VERSION 5.7 ;
BUSBITCHARS "[]" ;
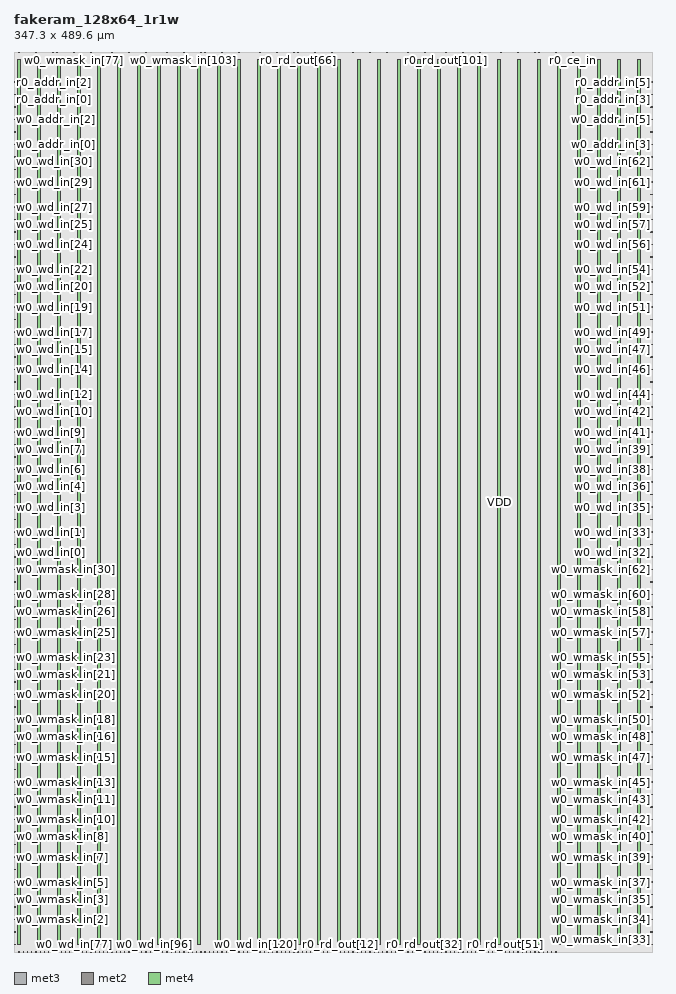
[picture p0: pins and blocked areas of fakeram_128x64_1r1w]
MACRO fakeram_128x64_1r1w
  FOREIGN fakeram_128x64_1r1w 0 0 ;
  SYMMETRY X Y R90 ;
  SIZE 347.300 BY 489.600 ;
  CLASS BLOCK ;
  PIN w0_wmask_in[0]
    DIRECTION INPUT ;
    USE SIGNAL ;
    SHAPE ABUTMENT ;
    PORT
      LAYER met3 ;
      RECT 0.000 3.930 0.900 4.230 ;
    END
  END w0_wmask_in[0]
  PIN w0_wmask_in[1]
    DIRECTION INPUT ;
    USE SIGNAL ;
    SHAPE ABUTMENT ;
    PORT
      LAYER met3 ;
      RECT 0.000 10.730 0.900 11.030 ;
    END
  END w0_wmask_in[1]
  PIN w0_wmask_in[2]
    DIRECTION INPUT ;
    USE SIGNAL ;
    SHAPE ABUTMENT ;
    PORT
      LAYER met3 ;
      RECT 0.000 17.530 0.900 17.830 ;
    END
  END w0_wmask_in[2]
  PIN w0_wmask_in[3]
    DIRECTION INPUT ;
    USE SIGNAL ;
    SHAPE ABUTMENT ;
    PORT
      LAYER met3 ;
      RECT 0.000 24.330 0.900 24.630 ;
    END
  END w0_wmask_in[3]
  PIN w0_wmask_in[4]
    DIRECTION INPUT ;
    USE SIGNAL ;
    SHAPE ABUTMENT ;
    PORT
      LAYER met3 ;
      RECT 0.000 31.130 0.900 31.430 ;
    END
  END w0_wmask_in[4]
  PIN w0_wmask_in[5]
    DIRECTION INPUT ;
    USE SIGNAL ;
    SHAPE ABUTMENT ;
    PORT
      LAYER met3 ;
      RECT 0.000 37.930 0.900 38.230 ;
    END
  END w0_wmask_in[5]
  PIN w0_wmask_in[6]
    DIRECTION INPUT ;
    USE SIGNAL ;
    SHAPE ABUTMENT ;
    PORT
      LAYER met3 ;
      RECT 0.000 44.730 0.900 45.030 ;
    END
  END w0_wmask_in[6]
  PIN w0_wmask_in[7]
    DIRECTION INPUT ;
    USE SIGNAL ;
    SHAPE ABUTMENT ;
    PORT
      LAYER met3 ;
      RECT 0.000 51.530 0.900 51.830 ;
    END
  END w0_wmask_in[7]
  PIN w0_wmask_in[8]
    DIRECTION INPUT ;
    USE SIGNAL ;
    SHAPE ABUTMENT ;
    PORT
      LAYER met3 ;
      RECT 0.000 58.330 0.900 58.630 ;
    END
  END w0_wmask_in[8]
  PIN w0_wmask_in[9]
    DIRECTION INPUT ;
    USE SIGNAL ;
    SHAPE ABUTMENT ;
    PORT
      LAYER met3 ;
      RECT 0.000 65.130 0.900 65.430 ;
    END
  END w0_wmask_in[9]
  PIN w0_wmask_in[10]
    DIRECTION INPUT ;
    USE SIGNAL ;
    SHAPE ABUTMENT ;
    PORT
      LAYER met3 ;
      RECT 0.000 71.930 0.900 72.230 ;
    END
  END w0_wmask_in[10]
  PIN w0_wmask_in[11]
    DIRECTION INPUT ;
    USE SIGNAL ;
    SHAPE ABUTMENT ;
    PORT
      LAYER met3 ;
      RECT 0.000 78.730 0.900 79.030 ;
    END
  END w0_wmask_in[11]
  PIN w0_wmask_in[12]
    DIRECTION INPUT ;
    USE SIGNAL ;
    SHAPE ABUTMENT ;
    PORT
      LAYER met3 ;
      RECT 0.000 85.530 0.900 85.830 ;
    END
  END w0_wmask_in[12]
  PIN w0_wmask_in[13]
    DIRECTION INPUT ;
    USE SIGNAL ;
    SHAPE ABUTMENT ;
    PORT
      LAYER met3 ;
      RECT 0.000 92.330 0.900 92.630 ;
    END
  END w0_wmask_in[13]
  PIN w0_wmask_in[14]
    DIRECTION INPUT ;
    USE SIGNAL ;
    SHAPE ABUTMENT ;
    PORT
      LAYER met3 ;
      RECT 0.000 99.130 0.900 99.430 ;
    END
  END w0_wmask_in[14]
  PIN w0_wmask_in[15]
    DIRECTION INPUT ;
    USE SIGNAL ;
    SHAPE ABUTMENT ;
    PORT
      LAYER met3 ;
      RECT 0.000 105.930 0.900 106.230 ;
    END
  END w0_wmask_in[15]
  PIN w0_wmask_in[16]
    DIRECTION INPUT ;
    USE SIGNAL ;
    SHAPE ABUTMENT ;
    PORT
      LAYER met3 ;
      RECT 0.000 112.730 0.900 113.030 ;
    END
  END w0_wmask_in[16]
  PIN w0_wmask_in[17]
    DIRECTION INPUT ;
    USE SIGNAL ;
    SHAPE ABUTMENT ;
    PORT
      LAYER met3 ;
      RECT 0.000 119.530 0.900 119.830 ;
    END
  END w0_wmask_in[17]
  PIN w0_wmask_in[18]
    DIRECTION INPUT ;
    USE SIGNAL ;
    SHAPE ABUTMENT ;
    PORT
      LAYER met3 ;
      RECT 0.000 126.330 0.900 126.630 ;
    END
  END w0_wmask_in[18]
  PIN w0_wmask_in[19]
    DIRECTION INPUT ;
    USE SIGNAL ;
    SHAPE ABUTMENT ;
    PORT
      LAYER met3 ;
      RECT 0.000 133.130 0.900 133.430 ;
    END
  END w0_wmask_in[19]
  PIN w0_wmask_in[20]
    DIRECTION INPUT ;
    USE SIGNAL ;
    SHAPE ABUTMENT ;
    PORT
      LAYER met3 ;
      RECT 0.000 139.930 0.900 140.230 ;
    END
  END w0_wmask_in[20]
  PIN w0_wmask_in[21]
    DIRECTION INPUT ;
    USE SIGNAL ;
    SHAPE ABUTMENT ;
    PORT
      LAYER met3 ;
      RECT 0.000 146.730 0.900 147.030 ;
    END
  END w0_wmask_in[21]
  PIN w0_wmask_in[22]
    DIRECTION INPUT ;
    USE SIGNAL ;
    SHAPE ABUTMENT ;
    PORT
      LAYER met3 ;
      RECT 0.000 153.530 0.900 153.830 ;
    END
  END w0_wmask_in[22]
  PIN w0_wmask_in[23]
    DIRECTION INPUT ;
    USE SIGNAL ;
    SHAPE ABUTMENT ;
    PORT
      LAYER met3 ;
      RECT 0.000 160.330 0.900 160.630 ;
    END
  END w0_wmask_in[23]
  PIN w0_wmask_in[24]
    DIRECTION INPUT ;
    USE SIGNAL ;
    SHAPE ABUTMENT ;
    PORT
      LAYER met3 ;
      RECT 0.000 167.130 0.900 167.430 ;
    END
  END w0_wmask_in[24]
  PIN w0_wmask_in[25]
    DIRECTION INPUT ;
    USE SIGNAL ;
    SHAPE ABUTMENT ;
    PORT
      LAYER met3 ;
      RECT 0.000 173.930 0.900 174.230 ;
    END
  END w0_wmask_in[25]
  PIN w0_wmask_in[26]
    DIRECTION INPUT ;
    USE SIGNAL ;
    SHAPE ABUTMENT ;
    PORT
      LAYER met3 ;
      RECT 0.000 180.730 0.900 181.030 ;
    END
  END w0_wmask_in[26]
  PIN w0_wmask_in[27]
    DIRECTION INPUT ;
    USE SIGNAL ;
    SHAPE ABUTMENT ;
    PORT
      LAYER met3 ;
      RECT 0.000 187.530 0.900 187.830 ;
    END
  END w0_wmask_in[27]
  PIN w0_wmask_in[28]
    DIRECTION INPUT ;
    USE SIGNAL ;
    SHAPE ABUTMENT ;
    PORT
      LAYER met3 ;
      RECT 0.000 194.330 0.900 194.630 ;
    END
  END w0_wmask_in[28]
  PIN w0_wmask_in[29]
    DIRECTION INPUT ;
    USE SIGNAL ;
    SHAPE ABUTMENT ;
    PORT
      LAYER met3 ;
      RECT 0.000 201.130 0.900 201.430 ;
    END
  END w0_wmask_in[29]
  PIN w0_wmask_in[30]
    DIRECTION INPUT ;
    USE SIGNAL ;
    SHAPE ABUTMENT ;
    PORT
      LAYER met3 ;
      RECT 0.000 207.930 0.900 208.230 ;
    END
  END w0_wmask_in[30]
  PIN w0_wmask_in[31]
    DIRECTION INPUT ;
    USE SIGNAL ;
    SHAPE ABUTMENT ;
    PORT
      LAYER met3 ;
      RECT 0.000 214.730 0.900 215.030 ;
    END
  END w0_wmask_in[31]
  PIN w0_wmask_in[32]
    DIRECTION INPUT ;
    USE SIGNAL ;
    SHAPE ABUTMENT ;
    PORT
      LAYER met3 ;
      RECT 346.400 3.930 347.300 4.230 ;
    END
  END w0_wmask_in[32]
  PIN w0_wmask_in[33]
    DIRECTION INPUT ;
    USE SIGNAL ;
    SHAPE ABUTMENT ;
    PORT
      LAYER met3 ;
      RECT 346.400 10.730 347.300 11.030 ;
    END
  END w0_wmask_in[33]
  PIN w0_wmask_in[34]
    DIRECTION INPUT ;
    USE SIGNAL ;
    SHAPE ABUTMENT ;
    PORT
      LAYER met3 ;
      RECT 346.400 17.530 347.300 17.830 ;
    END
  END w0_wmask_in[34]
  PIN w0_wmask_in[35]
    DIRECTION INPUT ;
    USE SIGNAL ;
    SHAPE ABUTMENT ;
    PORT
      LAYER met3 ;
      RECT 346.400 24.330 347.300 24.630 ;
    END
  END w0_wmask_in[35]
  PIN w0_wmask_in[36]
    DIRECTION INPUT ;
    USE SIGNAL ;
    SHAPE ABUTMENT ;
    PORT
      LAYER met3 ;
      RECT 346.400 31.130 347.300 31.430 ;
    END
  END w0_wmask_in[36]
  PIN w0_wmask_in[37]
    DIRECTION INPUT ;
    USE SIGNAL ;
    SHAPE ABUTMENT ;
    PORT
      LAYER met3 ;
      RECT 346.400 37.930 347.300 38.230 ;
    END
  END w0_wmask_in[37]
  PIN w0_wmask_in[38]
    DIRECTION INPUT ;
    USE SIGNAL ;
    SHAPE ABUTMENT ;
    PORT
      LAYER met3 ;
      RECT 346.400 44.730 347.300 45.030 ;
    END
  END w0_wmask_in[38]
  PIN w0_wmask_in[39]
    DIRECTION INPUT ;
    USE SIGNAL ;
    SHAPE ABUTMENT ;
    PORT
      LAYER met3 ;
      RECT 346.400 51.530 347.300 51.830 ;
    END
  END w0_wmask_in[39]
  PIN w0_wmask_in[40]
    DIRECTION INPUT ;
    USE SIGNAL ;
    SHAPE ABUTMENT ;
    PORT
      LAYER met3 ;
      RECT 346.400 58.330 347.300 58.630 ;
    END
  END w0_wmask_in[40]
  PIN w0_wmask_in[41]
    DIRECTION INPUT ;
    USE SIGNAL ;
    SHAPE ABUTMENT ;
    PORT
      LAYER met3 ;
      RECT 346.400 65.130 347.300 65.430 ;
    END
  END w0_wmask_in[41]
  PIN w0_wmask_in[42]
    DIRECTION INPUT ;
    USE SIGNAL ;
    SHAPE ABUTMENT ;
    PORT
      LAYER met3 ;
      RECT 346.400 71.930 347.300 72.230 ;
    END
  END w0_wmask_in[42]
  PIN w0_wmask_in[43]
    DIRECTION INPUT ;
    USE SIGNAL ;
    SHAPE ABUTMENT ;
    PORT
      LAYER met3 ;
      RECT 346.400 78.730 347.300 79.030 ;
    END
  END w0_wmask_in[43]
  PIN w0_wmask_in[44]
    DIRECTION INPUT ;
    USE SIGNAL ;
    SHAPE ABUTMENT ;
    PORT
      LAYER met3 ;
      RECT 346.400 85.530 347.300 85.830 ;
    END
  END w0_wmask_in[44]
  PIN w0_wmask_in[45]
    DIRECTION INPUT ;
    USE SIGNAL ;
    SHAPE ABUTMENT ;
    PORT
      LAYER met3 ;
      RECT 346.400 92.330 347.300 92.630 ;
    END
  END w0_wmask_in[45]
  PIN w0_wmask_in[46]
    DIRECTION INPUT ;
    USE SIGNAL ;
    SHAPE ABUTMENT ;
    PORT
      LAYER met3 ;
      RECT 346.400 99.130 347.300 99.430 ;
    END
  END w0_wmask_in[46]
  PIN w0_wmask_in[47]
    DIRECTION INPUT ;
    USE SIGNAL ;
    SHAPE ABUTMENT ;
    PORT
      LAYER met3 ;
      RECT 346.400 105.930 347.300 106.230 ;
    END
  END w0_wmask_in[47]
  PIN w0_wmask_in[48]
    DIRECTION INPUT ;
    USE SIGNAL ;
    SHAPE ABUTMENT ;
    PORT
      LAYER met3 ;
      RECT 346.400 112.730 347.300 113.030 ;
    END
  END w0_wmask_in[48]
  PIN w0_wmask_in[49]
    DIRECTION INPUT ;
    USE SIGNAL ;
    SHAPE ABUTMENT ;
    PORT
      LAYER met3 ;
      RECT 346.400 119.530 347.300 119.830 ;
    END
  END w0_wmask_in[49]
  PIN w0_wmask_in[50]
    DIRECTION INPUT ;
    USE SIGNAL ;
    SHAPE ABUTMENT ;
    PORT
      LAYER met3 ;
      RECT 346.400 126.330 347.300 126.630 ;
    END
  END w0_wmask_in[50]
  PIN w0_wmask_in[51]
    DIRECTION INPUT ;
    USE SIGNAL ;
    SHAPE ABUTMENT ;
    PORT
      LAYER met3 ;
      RECT 346.400 133.130 347.300 133.430 ;
    END
  END w0_wmask_in[51]
  PIN w0_wmask_in[52]
    DIRECTION INPUT ;
    USE SIGNAL ;
    SHAPE ABUTMENT ;
    PORT
      LAYER met3 ;
      RECT 346.400 139.930 347.300 140.230 ;
    END
  END w0_wmask_in[52]
  PIN w0_wmask_in[53]
    DIRECTION INPUT ;
    USE SIGNAL ;
    SHAPE ABUTMENT ;
    PORT
      LAYER met3 ;
      RECT 346.400 146.730 347.300 147.030 ;
    END
  END w0_wmask_in[53]
  PIN w0_wmask_in[54]
    DIRECTION INPUT ;
    USE SIGNAL ;
    SHAPE ABUTMENT ;
    PORT
      LAYER met3 ;
      RECT 346.400 153.530 347.300 153.830 ;
    END
  END w0_wmask_in[54]
  PIN w0_wmask_in[55]
    DIRECTION INPUT ;
    USE SIGNAL ;
    SHAPE ABUTMENT ;
    PORT
      LAYER met3 ;
      RECT 346.400 160.330 347.300 160.630 ;
    END
  END w0_wmask_in[55]
  PIN w0_wmask_in[56]
    DIRECTION INPUT ;
    USE SIGNAL ;
    SHAPE ABUTMENT ;
    PORT
      LAYER met3 ;
      RECT 346.400 167.130 347.300 167.430 ;
    END
  END w0_wmask_in[56]
  PIN w0_wmask_in[57]
    DIRECTION INPUT ;
    USE SIGNAL ;
    SHAPE ABUTMENT ;
    PORT
      LAYER met3 ;
      RECT 346.400 173.930 347.300 174.230 ;
    END
  END w0_wmask_in[57]
  PIN w0_wmask_in[58]
    DIRECTION INPUT ;
    USE SIGNAL ;
    SHAPE ABUTMENT ;
    PORT
      LAYER met3 ;
      RECT 346.400 180.730 347.300 181.030 ;
    END
  END w0_wmask_in[58]
  PIN w0_wmask_in[59]
    DIRECTION INPUT ;
    USE SIGNAL ;
    SHAPE ABUTMENT ;
    PORT
      LAYER met3 ;
      RECT 346.400 187.530 347.300 187.830 ;
    END
  END w0_wmask_in[59]
  PIN w0_wmask_in[60]
    DIRECTION INPUT ;
    USE SIGNAL ;
    SHAPE ABUTMENT ;
    PORT
      LAYER met3 ;
      RECT 346.400 194.330 347.300 194.630 ;
    END
  END w0_wmask_in[60]
  PIN w0_wmask_in[61]
    DIRECTION INPUT ;
    USE SIGNAL ;
    SHAPE ABUTMENT ;
    PORT
      LAYER met3 ;
      RECT 346.400 201.130 347.300 201.430 ;
    END
  END w0_wmask_in[61]
  PIN w0_wmask_in[62]
    DIRECTION INPUT ;
    USE SIGNAL ;
    SHAPE ABUTMENT ;
    PORT
      LAYER met3 ;
      RECT 346.400 207.930 347.300 208.230 ;
    END
  END w0_wmask_in[62]
  PIN w0_wmask_in[63]
    DIRECTION INPUT ;
    USE SIGNAL ;
    SHAPE ABUTMENT ;
    PORT
      LAYER met3 ;
      RECT 346.400 214.730 347.300 215.030 ;
    END
  END w0_wmask_in[63]
  PIN w0_wmask_in[64]
    DIRECTION INPUT ;
    USE SIGNAL ;
    SHAPE ABUTMENT ;
    PORT
      LAYER met2 ;
      RECT 2.690 489.180 2.830 489.600 ;
    END
  END w0_wmask_in[64]
  PIN w0_wmask_in[65]
    DIRECTION INPUT ;
    USE SIGNAL ;
    SHAPE ABUTMENT ;
    PORT
      LAYER met2 ;
      RECT 4.990 489.180 5.130 489.600 ;
    END
  END w0_wmask_in[65]
  PIN w0_wmask_in[66]
    DIRECTION INPUT ;
    USE SIGNAL ;
    SHAPE ABUTMENT ;
    PORT
      LAYER met2 ;
      RECT 7.290 489.180 7.430 489.600 ;
    END
  END w0_wmask_in[66]
  PIN w0_wmask_in[67]
    DIRECTION INPUT ;
    USE SIGNAL ;
    SHAPE ABUTMENT ;
    PORT
      LAYER met2 ;
      RECT 9.590 489.180 9.730 489.600 ;
    END
  END w0_wmask_in[67]
  PIN w0_wmask_in[68]
    DIRECTION INPUT ;
    USE SIGNAL ;
    SHAPE ABUTMENT ;
    PORT
      LAYER met2 ;
      RECT 11.890 489.180 12.030 489.600 ;
    END
  END w0_wmask_in[68]
  PIN w0_wmask_in[69]
    DIRECTION INPUT ;
    USE SIGNAL ;
    SHAPE ABUTMENT ;
    PORT
      LAYER met2 ;
      RECT 14.190 489.180 14.330 489.600 ;
    END
  END w0_wmask_in[69]
  PIN w0_wmask_in[70]
    DIRECTION INPUT ;
    USE SIGNAL ;
    SHAPE ABUTMENT ;
    PORT
      LAYER met2 ;
      RECT 16.490 489.180 16.630 489.600 ;
    END
  END w0_wmask_in[70]
  PIN w0_wmask_in[71]
    DIRECTION INPUT ;
    USE SIGNAL ;
    SHAPE ABUTMENT ;
    PORT
      LAYER met2 ;
      RECT 18.790 489.180 18.930 489.600 ;
    END
  END w0_wmask_in[71]
  PIN w0_wmask_in[72]
    DIRECTION INPUT ;
    USE SIGNAL ;
    SHAPE ABUTMENT ;
    PORT
      LAYER met2 ;
      RECT 21.090 489.180 21.230 489.600 ;
    END
  END w0_wmask_in[72]
  PIN w0_wmask_in[73]
    DIRECTION INPUT ;
    USE SIGNAL ;
    SHAPE ABUTMENT ;
    PORT
      LAYER met2 ;
      RECT 23.390 489.180 23.530 489.600 ;
    END
  END w0_wmask_in[73]
  PIN w0_wmask_in[74]
    DIRECTION INPUT ;
    USE SIGNAL ;
    SHAPE ABUTMENT ;
    PORT
      LAYER met2 ;
      RECT 25.690 489.180 25.830 489.600 ;
    END
  END w0_wmask_in[74]
  PIN w0_wmask_in[75]
    DIRECTION INPUT ;
    USE SIGNAL ;
    SHAPE ABUTMENT ;
    PORT
      LAYER met2 ;
      RECT 27.990 489.180 28.130 489.600 ;
    END
  END w0_wmask_in[75]
  PIN w0_wmask_in[76]
    DIRECTION INPUT ;
    USE SIGNAL ;
    SHAPE ABUTMENT ;
    PORT
      LAYER met2 ;
      RECT 30.290 489.180 30.430 489.600 ;
    END
  END w0_wmask_in[76]
  PIN w0_wmask_in[77]
    DIRECTION INPUT ;
    USE SIGNAL ;
    SHAPE ABUTMENT ;
    PORT
      LAYER met2 ;
      RECT 32.590 489.180 32.730 489.600 ;
    END
  END w0_wmask_in[77]
  PIN w0_wmask_in[78]
    DIRECTION INPUT ;
    USE SIGNAL ;
    SHAPE ABUTMENT ;
    PORT
      LAYER met2 ;
      RECT 34.890 489.180 35.030 489.600 ;
    END
  END w0_wmask_in[78]
  PIN w0_wmask_in[79]
    DIRECTION INPUT ;
    USE SIGNAL ;
    SHAPE ABUTMENT ;
    PORT
      LAYER met2 ;
      RECT 37.190 489.180 37.330 489.600 ;
    END
  END w0_wmask_in[79]
  PIN w0_wmask_in[80]
    DIRECTION INPUT ;
    USE SIGNAL ;
    SHAPE ABUTMENT ;
    PORT
      LAYER met2 ;
      RECT 39.490 489.180 39.630 489.600 ;
    END
  END w0_wmask_in[80]
  PIN w0_wmask_in[81]
    DIRECTION INPUT ;
    USE SIGNAL ;
    SHAPE ABUTMENT ;
    PORT
      LAYER met2 ;
      RECT 41.790 489.180 41.930 489.600 ;
    END
  END w0_wmask_in[81]
  PIN w0_wmask_in[82]
    DIRECTION INPUT ;
    USE SIGNAL ;
    SHAPE ABUTMENT ;
    PORT
      LAYER met2 ;
      RECT 44.090 489.180 44.230 489.600 ;
    END
  END w0_wmask_in[82]
  PIN w0_wmask_in[83]
    DIRECTION INPUT ;
    USE SIGNAL ;
    SHAPE ABUTMENT ;
    PORT
      LAYER met2 ;
      RECT 46.390 489.180 46.530 489.600 ;
    END
  END w0_wmask_in[83]
  PIN w0_wmask_in[84]
    DIRECTION INPUT ;
    USE SIGNAL ;
    SHAPE ABUTMENT ;
    PORT
      LAYER met2 ;
      RECT 48.690 489.180 48.830 489.600 ;
    END
  END w0_wmask_in[84]
  PIN w0_wmask_in[85]
    DIRECTION INPUT ;
    USE SIGNAL ;
    SHAPE ABUTMENT ;
    PORT
      LAYER met2 ;
      RECT 50.990 489.180 51.130 489.600 ;
    END
  END w0_wmask_in[85]
  PIN w0_wmask_in[86]
    DIRECTION INPUT ;
    USE SIGNAL ;
    SHAPE ABUTMENT ;
    PORT
      LAYER met2 ;
      RECT 53.290 489.180 53.430 489.600 ;
    END
  END w0_wmask_in[86]
  PIN w0_wmask_in[87]
    DIRECTION INPUT ;
    USE SIGNAL ;
    SHAPE ABUTMENT ;
    PORT
      LAYER met2 ;
      RECT 55.590 489.180 55.730 489.600 ;
    END
  END w0_wmask_in[87]
  PIN w0_wmask_in[88]
    DIRECTION INPUT ;
    USE SIGNAL ;
    SHAPE ABUTMENT ;
    PORT
      LAYER met2 ;
      RECT 57.890 489.180 58.030 489.600 ;
    END
  END w0_wmask_in[88]
  PIN w0_wmask_in[89]
    DIRECTION INPUT ;
    USE SIGNAL ;
    SHAPE ABUTMENT ;
    PORT
      LAYER met2 ;
      RECT 60.190 489.180 60.330 489.600 ;
    END
  END w0_wmask_in[89]
  PIN w0_wmask_in[90]
    DIRECTION INPUT ;
    USE SIGNAL ;
    SHAPE ABUTMENT ;
    PORT
      LAYER met2 ;
      RECT 62.490 489.180 62.630 489.600 ;
    END
  END w0_wmask_in[90]
  PIN w0_wmask_in[91]
    DIRECTION INPUT ;
    USE SIGNAL ;
    SHAPE ABUTMENT ;
    PORT
      LAYER met2 ;
      RECT 64.790 489.180 64.930 489.600 ;
    END
  END w0_wmask_in[91]
  PIN w0_wmask_in[92]
    DIRECTION INPUT ;
    USE SIGNAL ;
    SHAPE ABUTMENT ;
    PORT
      LAYER met2 ;
      RECT 67.090 489.180 67.230 489.600 ;
    END
  END w0_wmask_in[92]
  PIN w0_wmask_in[93]
    DIRECTION INPUT ;
    USE SIGNAL ;
    SHAPE ABUTMENT ;
    PORT
      LAYER met2 ;
      RECT 69.390 489.180 69.530 489.600 ;
    END
  END w0_wmask_in[93]
  PIN w0_wmask_in[94]
    DIRECTION INPUT ;
    USE SIGNAL ;
    SHAPE ABUTMENT ;
    PORT
      LAYER met2 ;
      RECT 71.690 489.180 71.830 489.600 ;
    END
  END w0_wmask_in[94]
  PIN w0_wmask_in[95]
    DIRECTION INPUT ;
    USE SIGNAL ;
    SHAPE ABUTMENT ;
    PORT
      LAYER met2 ;
      RECT 73.990 489.180 74.130 489.600 ;
    END
  END w0_wmask_in[95]
  PIN w0_wmask_in[96]
    DIRECTION INPUT ;
    USE SIGNAL ;
    SHAPE ABUTMENT ;
    PORT
      LAYER met2 ;
      RECT 76.290 489.180 76.430 489.600 ;
    END
  END w0_wmask_in[96]
  PIN w0_wmask_in[97]
    DIRECTION INPUT ;
    USE SIGNAL ;
    SHAPE ABUTMENT ;
    PORT
      LAYER met2 ;
      RECT 78.590 489.180 78.730 489.600 ;
    END
  END w0_wmask_in[97]
  PIN w0_wmask_in[98]
    DIRECTION INPUT ;
    USE SIGNAL ;
    SHAPE ABUTMENT ;
    PORT
      LAYER met2 ;
      RECT 80.890 489.180 81.030 489.600 ;
    END
  END w0_wmask_in[98]
  PIN w0_wmask_in[99]
    DIRECTION INPUT ;
    USE SIGNAL ;
    SHAPE ABUTMENT ;
    PORT
      LAYER met2 ;
      RECT 83.190 489.180 83.330 489.600 ;
    END
  END w0_wmask_in[99]
  PIN w0_wmask_in[100]
    DIRECTION INPUT ;
    USE SIGNAL ;
    SHAPE ABUTMENT ;
    PORT
      LAYER met2 ;
      RECT 85.490 489.180 85.630 489.600 ;
    END
  END w0_wmask_in[100]
  PIN w0_wmask_in[101]
    DIRECTION INPUT ;
    USE SIGNAL ;
    SHAPE ABUTMENT ;
    PORT
      LAYER met2 ;
      RECT 87.790 489.180 87.930 489.600 ;
    END
  END w0_wmask_in[101]
  PIN w0_wmask_in[102]
    DIRECTION INPUT ;
    USE SIGNAL ;
    SHAPE ABUTMENT ;
    PORT
      LAYER met2 ;
      RECT 90.090 489.180 90.230 489.600 ;
    END
  END w0_wmask_in[102]
  PIN w0_wmask_in[103]
    DIRECTION INPUT ;
    USE SIGNAL ;
    SHAPE ABUTMENT ;
    PORT
      LAYER met2 ;
      RECT 92.390 489.180 92.530 489.600 ;
    END
  END w0_wmask_in[103]
  PIN w0_wmask_in[104]
    DIRECTION INPUT ;
    USE SIGNAL ;
    SHAPE ABUTMENT ;
    PORT
      LAYER met2 ;
      RECT 94.690 489.180 94.830 489.600 ;
    END
  END w0_wmask_in[104]
  PIN w0_wmask_in[105]
    DIRECTION INPUT ;
    USE SIGNAL ;
    SHAPE ABUTMENT ;
    PORT
      LAYER met2 ;
      RECT 96.990 489.180 97.130 489.600 ;
    END
  END w0_wmask_in[105]
  PIN w0_wmask_in[106]
    DIRECTION INPUT ;
    USE SIGNAL ;
    SHAPE ABUTMENT ;
    PORT
      LAYER met2 ;
      RECT 99.290 489.180 99.430 489.600 ;
    END
  END w0_wmask_in[106]
  PIN w0_wmask_in[107]
    DIRECTION INPUT ;
    USE SIGNAL ;
    SHAPE ABUTMENT ;
    PORT
      LAYER met2 ;
      RECT 101.590 489.180 101.730 489.600 ;
    END
  END w0_wmask_in[107]
  PIN w0_wmask_in[108]
    DIRECTION INPUT ;
    USE SIGNAL ;
    SHAPE ABUTMENT ;
    PORT
      LAYER met2 ;
      RECT 103.890 489.180 104.030 489.600 ;
    END
  END w0_wmask_in[108]
  PIN w0_wmask_in[109]
    DIRECTION INPUT ;
    USE SIGNAL ;
    SHAPE ABUTMENT ;
    PORT
      LAYER met2 ;
      RECT 106.190 489.180 106.330 489.600 ;
    END
  END w0_wmask_in[109]
  PIN w0_wmask_in[110]
    DIRECTION INPUT ;
    USE SIGNAL ;
    SHAPE ABUTMENT ;
    PORT
      LAYER met2 ;
      RECT 108.490 489.180 108.630 489.600 ;
    END
  END w0_wmask_in[110]
  PIN w0_wmask_in[111]
    DIRECTION INPUT ;
    USE SIGNAL ;
    SHAPE ABUTMENT ;
    PORT
      LAYER met2 ;
      RECT 110.790 489.180 110.930 489.600 ;
    END
  END w0_wmask_in[111]
  PIN w0_wmask_in[112]
    DIRECTION INPUT ;
    USE SIGNAL ;
    SHAPE ABUTMENT ;
    PORT
      LAYER met2 ;
      RECT 113.090 489.180 113.230 489.600 ;
    END
  END w0_wmask_in[112]
  PIN w0_wmask_in[113]
    DIRECTION INPUT ;
    USE SIGNAL ;
    SHAPE ABUTMENT ;
    PORT
      LAYER met2 ;
      RECT 115.390 489.180 115.530 489.600 ;
    END
  END w0_wmask_in[113]
  PIN w0_wmask_in[114]
    DIRECTION INPUT ;
    USE SIGNAL ;
    SHAPE ABUTMENT ;
    PORT
      LAYER met2 ;
      RECT 117.690 489.180 117.830 489.600 ;
    END
  END w0_wmask_in[114]
  PIN w0_wmask_in[115]
    DIRECTION INPUT ;
    USE SIGNAL ;
    SHAPE ABUTMENT ;
    PORT
      LAYER met2 ;
      RECT 119.990 489.180 120.130 489.600 ;
    END
  END w0_wmask_in[115]
  PIN w0_wmask_in[116]
    DIRECTION INPUT ;
    USE SIGNAL ;
    SHAPE ABUTMENT ;
    PORT
      LAYER met2 ;
      RECT 122.290 489.180 122.430 489.600 ;
    END
  END w0_wmask_in[116]
  PIN w0_wmask_in[117]
    DIRECTION INPUT ;
    USE SIGNAL ;
    SHAPE ABUTMENT ;
    PORT
      LAYER met2 ;
      RECT 124.590 489.180 124.730 489.600 ;
    END
  END w0_wmask_in[117]
  PIN w0_wmask_in[118]
    DIRECTION INPUT ;
    USE SIGNAL ;
    SHAPE ABUTMENT ;
    PORT
      LAYER met2 ;
      RECT 126.890 489.180 127.030 489.600 ;
    END
  END w0_wmask_in[118]
  PIN w0_wmask_in[119]
    DIRECTION INPUT ;
    USE SIGNAL ;
    SHAPE ABUTMENT ;
    PORT
      LAYER met2 ;
      RECT 129.190 489.180 129.330 489.600 ;
    END
  END w0_wmask_in[119]
  PIN w0_wmask_in[120]
    DIRECTION INPUT ;
    USE SIGNAL ;
    SHAPE ABUTMENT ;
    PORT
      LAYER met2 ;
      RECT 131.490 489.180 131.630 489.600 ;
    END
  END w0_wmask_in[120]
  PIN w0_wmask_in[121]
    DIRECTION INPUT ;
    USE SIGNAL ;
    SHAPE ABUTMENT ;
    PORT
      LAYER met2 ;
      RECT 133.790 489.180 133.930 489.600 ;
    END
  END w0_wmask_in[121]
  PIN w0_wmask_in[122]
    DIRECTION INPUT ;
    USE SIGNAL ;
    SHAPE ABUTMENT ;
    PORT
      LAYER met2 ;
      RECT 136.090 489.180 136.230 489.600 ;
    END
  END w0_wmask_in[122]
  PIN w0_wmask_in[123]
    DIRECTION INPUT ;
    USE SIGNAL ;
    SHAPE ABUTMENT ;
    PORT
      LAYER met2 ;
      RECT 138.390 489.180 138.530 489.600 ;
    END
  END w0_wmask_in[123]
  PIN w0_wmask_in[124]
    DIRECTION INPUT ;
    USE SIGNAL ;
    SHAPE ABUTMENT ;
    PORT
      LAYER met2 ;
      RECT 140.690 489.180 140.830 489.600 ;
    END
  END w0_wmask_in[124]
  PIN w0_wmask_in[125]
    DIRECTION INPUT ;
    USE SIGNAL ;
    SHAPE ABUTMENT ;
    PORT
      LAYER met2 ;
      RECT 142.990 489.180 143.130 489.600 ;
    END
  END w0_wmask_in[125]
  PIN w0_wmask_in[126]
    DIRECTION INPUT ;
    USE SIGNAL ;
    SHAPE ABUTMENT ;
    PORT
      LAYER met2 ;
      RECT 145.290 489.180 145.430 489.600 ;
    END
  END w0_wmask_in[126]
  PIN w0_wmask_in[127]
    DIRECTION INPUT ;
    USE SIGNAL ;
    SHAPE ABUTMENT ;
    PORT
      LAYER met2 ;
      RECT 147.590 489.180 147.730 489.600 ;
    END
  END w0_wmask_in[127]
  PIN w0_wd_in[0]
    DIRECTION INPUT ;
    USE SIGNAL ;
    SHAPE ABUTMENT ;
    PORT
      LAYER met3 ;
      RECT 0.000 221.530 0.900 221.830 ;
    END
  END w0_wd_in[0]
  PIN w0_wd_in[1]
    DIRECTION INPUT ;
    USE SIGNAL ;
    SHAPE ABUTMENT ;
    PORT
      LAYER met3 ;
      RECT 0.000 228.330 0.900 228.630 ;
    END
  END w0_wd_in[1]
  PIN w0_wd_in[2]
    DIRECTION INPUT ;
    USE SIGNAL ;
    SHAPE ABUTMENT ;
    PORT
      LAYER met3 ;
      RECT 0.000 235.130 0.900 235.430 ;
    END
  END w0_wd_in[2]
  PIN w0_wd_in[3]
    DIRECTION INPUT ;
    USE SIGNAL ;
    SHAPE ABUTMENT ;
    PORT
      LAYER met3 ;
      RECT 0.000 241.930 0.900 242.230 ;
    END
  END w0_wd_in[3]
  PIN w0_wd_in[4]
    DIRECTION INPUT ;
    USE SIGNAL ;
    SHAPE ABUTMENT ;
    PORT
      LAYER met3 ;
      RECT 0.000 248.730 0.900 249.030 ;
    END
  END w0_wd_in[4]
  PIN w0_wd_in[5]
    DIRECTION INPUT ;
    USE SIGNAL ;
    SHAPE ABUTMENT ;
    PORT
      LAYER met3 ;
      RECT 0.000 255.530 0.900 255.830 ;
    END
  END w0_wd_in[5]
  PIN w0_wd_in[6]
    DIRECTION INPUT ;
    USE SIGNAL ;
    SHAPE ABUTMENT ;
    PORT
      LAYER met3 ;
      RECT 0.000 262.330 0.900 262.630 ;
    END
  END w0_wd_in[6]
  PIN w0_wd_in[7]
    DIRECTION INPUT ;
    USE SIGNAL ;
    SHAPE ABUTMENT ;
    PORT
      LAYER met3 ;
      RECT 0.000 269.130 0.900 269.430 ;
    END
  END w0_wd_in[7]
  PIN w0_wd_in[8]
    DIRECTION INPUT ;
    USE SIGNAL ;
    SHAPE ABUTMENT ;
    PORT
      LAYER met3 ;
      RECT 0.000 275.930 0.900 276.230 ;
    END
  END w0_wd_in[8]
  PIN w0_wd_in[9]
    DIRECTION INPUT ;
    USE SIGNAL ;
    SHAPE ABUTMENT ;
    PORT
      LAYER met3 ;
      RECT 0.000 282.730 0.900 283.030 ;
    END
  END w0_wd_in[9]
  PIN w0_wd_in[10]
    DIRECTION INPUT ;
    USE SIGNAL ;
    SHAPE ABUTMENT ;
    PORT
      LAYER met3 ;
      RECT 0.000 289.530 0.900 289.830 ;
    END
  END w0_wd_in[10]
  PIN w0_wd_in[11]
    DIRECTION INPUT ;
    USE SIGNAL ;
    SHAPE ABUTMENT ;
    PORT
      LAYER met3 ;
      RECT 0.000 296.330 0.900 296.630 ;
    END
  END w0_wd_in[11]
  PIN w0_wd_in[12]
    DIRECTION INPUT ;
    USE SIGNAL ;
    SHAPE ABUTMENT ;
    PORT
      LAYER met3 ;
      RECT 0.000 303.130 0.900 303.430 ;
    END
  END w0_wd_in[12]
  PIN w0_wd_in[13]
    DIRECTION INPUT ;
    USE SIGNAL ;
    SHAPE ABUTMENT ;
    PORT
      LAYER met3 ;
      RECT 0.000 309.930 0.900 310.230 ;
    END
  END w0_wd_in[13]
  PIN w0_wd_in[14]
    DIRECTION INPUT ;
    USE SIGNAL ;
    SHAPE ABUTMENT ;
    PORT
      LAYER met3 ;
      RECT 0.000 316.730 0.900 317.030 ;
    END
  END w0_wd_in[14]
  PIN w0_wd_in[15]
    DIRECTION INPUT ;
    USE SIGNAL ;
    SHAPE ABUTMENT ;
    PORT
      LAYER met3 ;
      RECT 0.000 323.530 0.900 323.830 ;
    END
  END w0_wd_in[15]
  PIN w0_wd_in[16]
    DIRECTION INPUT ;
    USE SIGNAL ;
    SHAPE ABUTMENT ;
    PORT
      LAYER met3 ;
      RECT 0.000 330.330 0.900 330.630 ;
    END
  END w0_wd_in[16]
  PIN w0_wd_in[17]
    DIRECTION INPUT ;
    USE SIGNAL ;
    SHAPE ABUTMENT ;
    PORT
      LAYER met3 ;
      RECT 0.000 337.130 0.900 337.430 ;
    END
  END w0_wd_in[17]
  PIN w0_wd_in[18]
    DIRECTION INPUT ;
    USE SIGNAL ;
    SHAPE ABUTMENT ;
    PORT
      LAYER met3 ;
      RECT 0.000 343.930 0.900 344.230 ;
    END
  END w0_wd_in[18]
  PIN w0_wd_in[19]
    DIRECTION INPUT ;
    USE SIGNAL ;
    SHAPE ABUTMENT ;
    PORT
      LAYER met3 ;
      RECT 0.000 350.730 0.900 351.030 ;
    END
  END w0_wd_in[19]
  PIN w0_wd_in[20]
    DIRECTION INPUT ;
    USE SIGNAL ;
    SHAPE ABUTMENT ;
    PORT
      LAYER met3 ;
      RECT 0.000 357.530 0.900 357.830 ;
    END
  END w0_wd_in[20]
  PIN w0_wd_in[21]
    DIRECTION INPUT ;
    USE SIGNAL ;
    SHAPE ABUTMENT ;
    PORT
      LAYER met3 ;
      RECT 0.000 364.330 0.900 364.630 ;
    END
  END w0_wd_in[21]
  PIN w0_wd_in[22]
    DIRECTION INPUT ;
    USE SIGNAL ;
    SHAPE ABUTMENT ;
    PORT
      LAYER met3 ;
      RECT 0.000 371.130 0.900 371.430 ;
    END
  END w0_wd_in[22]
  PIN w0_wd_in[23]
    DIRECTION INPUT ;
    USE SIGNAL ;
    SHAPE ABUTMENT ;
    PORT
      LAYER met3 ;
      RECT 0.000 377.930 0.900 378.230 ;
    END
  END w0_wd_in[23]
  PIN w0_wd_in[24]
    DIRECTION INPUT ;
    USE SIGNAL ;
    SHAPE ABUTMENT ;
    PORT
      LAYER met3 ;
      RECT 0.000 384.730 0.900 385.030 ;
    END
  END w0_wd_in[24]
  PIN w0_wd_in[25]
    DIRECTION INPUT ;
    USE SIGNAL ;
    SHAPE ABUTMENT ;
    PORT
      LAYER met3 ;
      RECT 0.000 391.530 0.900 391.830 ;
    END
  END w0_wd_in[25]
  PIN w0_wd_in[26]
    DIRECTION INPUT ;
    USE SIGNAL ;
    SHAPE ABUTMENT ;
    PORT
      LAYER met3 ;
      RECT 0.000 398.330 0.900 398.630 ;
    END
  END w0_wd_in[26]
  PIN w0_wd_in[27]
    DIRECTION INPUT ;
    USE SIGNAL ;
    SHAPE ABUTMENT ;
    PORT
      LAYER met3 ;
      RECT 0.000 405.130 0.900 405.430 ;
    END
  END w0_wd_in[27]
  PIN w0_wd_in[28]
    DIRECTION INPUT ;
    USE SIGNAL ;
    SHAPE ABUTMENT ;
    PORT
      LAYER met3 ;
      RECT 0.000 411.930 0.900 412.230 ;
    END
  END w0_wd_in[28]
  PIN w0_wd_in[29]
    DIRECTION INPUT ;
    USE SIGNAL ;
    SHAPE ABUTMENT ;
    PORT
      LAYER met3 ;
      RECT 0.000 418.730 0.900 419.030 ;
    END
  END w0_wd_in[29]
  PIN w0_wd_in[30]
    DIRECTION INPUT ;
    USE SIGNAL ;
    SHAPE ABUTMENT ;
    PORT
      LAYER met3 ;
      RECT 0.000 425.530 0.900 425.830 ;
    END
  END w0_wd_in[30]
  PIN w0_wd_in[31]
    DIRECTION INPUT ;
    USE SIGNAL ;
    SHAPE ABUTMENT ;
    PORT
      LAYER met3 ;
      RECT 0.000 432.330 0.900 432.630 ;
    END
  END w0_wd_in[31]
  PIN w0_wd_in[32]
    DIRECTION INPUT ;
    USE SIGNAL ;
    SHAPE ABUTMENT ;
    PORT
      LAYER met3 ;
      RECT 346.400 221.530 347.300 221.830 ;
    END
  END w0_wd_in[32]
  PIN w0_wd_in[33]
    DIRECTION INPUT ;
    USE SIGNAL ;
    SHAPE ABUTMENT ;
    PORT
      LAYER met3 ;
      RECT 346.400 228.330 347.300 228.630 ;
    END
  END w0_wd_in[33]
  PIN w0_wd_in[34]
    DIRECTION INPUT ;
    USE SIGNAL ;
    SHAPE ABUTMENT ;
    PORT
      LAYER met3 ;
      RECT 346.400 235.130 347.300 235.430 ;
    END
  END w0_wd_in[34]
  PIN w0_wd_in[35]
    DIRECTION INPUT ;
    USE SIGNAL ;
    SHAPE ABUTMENT ;
    PORT
      LAYER met3 ;
      RECT 346.400 241.930 347.300 242.230 ;
    END
  END w0_wd_in[35]
  PIN w0_wd_in[36]
    DIRECTION INPUT ;
    USE SIGNAL ;
    SHAPE ABUTMENT ;
    PORT
      LAYER met3 ;
      RECT 346.400 248.730 347.300 249.030 ;
    END
  END w0_wd_in[36]
  PIN w0_wd_in[37]
    DIRECTION INPUT ;
    USE SIGNAL ;
    SHAPE ABUTMENT ;
    PORT
      LAYER met3 ;
      RECT 346.400 255.530 347.300 255.830 ;
    END
  END w0_wd_in[37]
  PIN w0_wd_in[38]
    DIRECTION INPUT ;
    USE SIGNAL ;
    SHAPE ABUTMENT ;
    PORT
      LAYER met3 ;
      RECT 346.400 262.330 347.300 262.630 ;
    END
  END w0_wd_in[38]
  PIN w0_wd_in[39]
    DIRECTION INPUT ;
    USE SIGNAL ;
    SHAPE ABUTMENT ;
    PORT
      LAYER met3 ;
      RECT 346.400 269.130 347.300 269.430 ;
    END
  END w0_wd_in[39]
  PIN w0_wd_in[40]
    DIRECTION INPUT ;
    USE SIGNAL ;
    SHAPE ABUTMENT ;
    PORT
      LAYER met3 ;
      RECT 346.400 275.930 347.300 276.230 ;
    END
  END w0_wd_in[40]
  PIN w0_wd_in[41]
    DIRECTION INPUT ;
    USE SIGNAL ;
    SHAPE ABUTMENT ;
    PORT
      LAYER met3 ;
      RECT 346.400 282.730 347.300 283.030 ;
    END
  END w0_wd_in[41]
  PIN w0_wd_in[42]
    DIRECTION INPUT ;
    USE SIGNAL ;
    SHAPE ABUTMENT ;
    PORT
      LAYER met3 ;
      RECT 346.400 289.530 347.300 289.830 ;
    END
  END w0_wd_in[42]
  PIN w0_wd_in[43]
    DIRECTION INPUT ;
    USE SIGNAL ;
    SHAPE ABUTMENT ;
    PORT
      LAYER met3 ;
      RECT 346.400 296.330 347.300 296.630 ;
    END
  END w0_wd_in[43]
  PIN w0_wd_in[44]
    DIRECTION INPUT ;
    USE SIGNAL ;
    SHAPE ABUTMENT ;
    PORT
      LAYER met3 ;
      RECT 346.400 303.130 347.300 303.430 ;
    END
  END w0_wd_in[44]
  PIN w0_wd_in[45]
    DIRECTION INPUT ;
    USE SIGNAL ;
    SHAPE ABUTMENT ;
    PORT
      LAYER met3 ;
      RECT 346.400 309.930 347.300 310.230 ;
    END
  END w0_wd_in[45]
  PIN w0_wd_in[46]
    DIRECTION INPUT ;
    USE SIGNAL ;
    SHAPE ABUTMENT ;
    PORT
      LAYER met3 ;
      RECT 346.400 316.730 347.300 317.030 ;
    END
  END w0_wd_in[46]
  PIN w0_wd_in[47]
    DIRECTION INPUT ;
    USE SIGNAL ;
    SHAPE ABUTMENT ;
    PORT
      LAYER met3 ;
      RECT 346.400 323.530 347.300 323.830 ;
    END
  END w0_wd_in[47]
  PIN w0_wd_in[48]
    DIRECTION INPUT ;
    USE SIGNAL ;
    SHAPE ABUTMENT ;
    PORT
      LAYER met3 ;
      RECT 346.400 330.330 347.300 330.630 ;
    END
  END w0_wd_in[48]
  PIN w0_wd_in[49]
    DIRECTION INPUT ;
    USE SIGNAL ;
    SHAPE ABUTMENT ;
    PORT
      LAYER met3 ;
      RECT 346.400 337.130 347.300 337.430 ;
    END
  END w0_wd_in[49]
  PIN w0_wd_in[50]
    DIRECTION INPUT ;
    USE SIGNAL ;
    SHAPE ABUTMENT ;
    PORT
      LAYER met3 ;
      RECT 346.400 343.930 347.300 344.230 ;
    END
  END w0_wd_in[50]
  PIN w0_wd_in[51]
    DIRECTION INPUT ;
    USE SIGNAL ;
    SHAPE ABUTMENT ;
    PORT
      LAYER met3 ;
      RECT 346.400 350.730 347.300 351.030 ;
    END
  END w0_wd_in[51]
  PIN w0_wd_in[52]
    DIRECTION INPUT ;
    USE SIGNAL ;
    SHAPE ABUTMENT ;
    PORT
      LAYER met3 ;
      RECT 346.400 357.530 347.300 357.830 ;
    END
  END w0_wd_in[52]
  PIN w0_wd_in[53]
    DIRECTION INPUT ;
    USE SIGNAL ;
    SHAPE ABUTMENT ;
    PORT
      LAYER met3 ;
      RECT 346.400 364.330 347.300 364.630 ;
    END
  END w0_wd_in[53]
  PIN w0_wd_in[54]
    DIRECTION INPUT ;
    USE SIGNAL ;
    SHAPE ABUTMENT ;
    PORT
      LAYER met3 ;
      RECT 346.400 371.130 347.300 371.430 ;
    END
  END w0_wd_in[54]
  PIN w0_wd_in[55]
    DIRECTION INPUT ;
    USE SIGNAL ;
    SHAPE ABUTMENT ;
    PORT
      LAYER met3 ;
      RECT 346.400 377.930 347.300 378.230 ;
    END
  END w0_wd_in[55]
  PIN w0_wd_in[56]
    DIRECTION INPUT ;
    USE SIGNAL ;
    SHAPE ABUTMENT ;
    PORT
      LAYER met3 ;
      RECT 346.400 384.730 347.300 385.030 ;
    END
  END w0_wd_in[56]
  PIN w0_wd_in[57]
    DIRECTION INPUT ;
    USE SIGNAL ;
    SHAPE ABUTMENT ;
    PORT
      LAYER met3 ;
      RECT 346.400 391.530 347.300 391.830 ;
    END
  END w0_wd_in[57]
  PIN w0_wd_in[58]
    DIRECTION INPUT ;
    USE SIGNAL ;
    SHAPE ABUTMENT ;
    PORT
      LAYER met3 ;
      RECT 346.400 398.330 347.300 398.630 ;
    END
  END w0_wd_in[58]
  PIN w0_wd_in[59]
    DIRECTION INPUT ;
    USE SIGNAL ;
    SHAPE ABUTMENT ;
    PORT
      LAYER met3 ;
      RECT 346.400 405.130 347.300 405.430 ;
    END
  END w0_wd_in[59]
  PIN w0_wd_in[60]
    DIRECTION INPUT ;
    USE SIGNAL ;
    SHAPE ABUTMENT ;
    PORT
      LAYER met3 ;
      RECT 346.400 411.930 347.300 412.230 ;
    END
  END w0_wd_in[60]
  PIN w0_wd_in[61]
    DIRECTION INPUT ;
    USE SIGNAL ;
    SHAPE ABUTMENT ;
    PORT
      LAYER met3 ;
      RECT 346.400 418.730 347.300 419.030 ;
    END
  END w0_wd_in[61]
  PIN w0_wd_in[62]
    DIRECTION INPUT ;
    USE SIGNAL ;
    SHAPE ABUTMENT ;
    PORT
      LAYER met3 ;
      RECT 346.400 425.530 347.300 425.830 ;
    END
  END w0_wd_in[62]
  PIN w0_wd_in[63]
    DIRECTION INPUT ;
    USE SIGNAL ;
    SHAPE ABUTMENT ;
    PORT
      LAYER met3 ;
      RECT 346.400 432.330 347.300 432.630 ;
    END
  END w0_wd_in[63]
  PIN w0_wd_in[64]
    DIRECTION OUTPUT ;
    USE SIGNAL ;
    SHAPE ABUTMENT ;
    PORT
      LAYER met2 ;
      RECT 2.690 0.000 2.830 0.420 ;
    END
  END w0_wd_in[64]
  PIN w0_wd_in[65]
    DIRECTION OUTPUT ;
    USE SIGNAL ;
    SHAPE ABUTMENT ;
    PORT
      LAYER met2 ;
      RECT 4.990 0.000 5.130 0.420 ;
    END
  END w0_wd_in[65]
  PIN w0_wd_in[66]
    DIRECTION OUTPUT ;
    USE SIGNAL ;
    SHAPE ABUTMENT ;
    PORT
      LAYER met2 ;
      RECT 7.290 0.000 7.430 0.420 ;
    END
  END w0_wd_in[66]
  PIN w0_wd_in[67]
    DIRECTION OUTPUT ;
    USE SIGNAL ;
    SHAPE ABUTMENT ;
    PORT
      LAYER met2 ;
      RECT 9.590 0.000 9.730 0.420 ;
    END
  END w0_wd_in[67]
  PIN w0_wd_in[68]
    DIRECTION OUTPUT ;
    USE SIGNAL ;
    SHAPE ABUTMENT ;
    PORT
      LAYER met2 ;
      RECT 11.890 0.000 12.030 0.420 ;
    END
  END w0_wd_in[68]
  PIN w0_wd_in[69]
    DIRECTION OUTPUT ;
    USE SIGNAL ;
    SHAPE ABUTMENT ;
    PORT
      LAYER met2 ;
      RECT 14.190 0.000 14.330 0.420 ;
    END
  END w0_wd_in[69]
  PIN w0_wd_in[70]
    DIRECTION OUTPUT ;
    USE SIGNAL ;
    SHAPE ABUTMENT ;
    PORT
      LAYER met2 ;
      RECT 16.490 0.000 16.630 0.420 ;
    END
  END w0_wd_in[70]
  PIN w0_wd_in[71]
    DIRECTION OUTPUT ;
    USE SIGNAL ;
    SHAPE ABUTMENT ;
    PORT
      LAYER met2 ;
      RECT 18.790 0.000 18.930 0.420 ;
    END
  END w0_wd_in[71]
  PIN w0_wd_in[72]
    DIRECTION OUTPUT ;
    USE SIGNAL ;
    SHAPE ABUTMENT ;
    PORT
      LAYER met2 ;
      RECT 21.090 0.000 21.230 0.420 ;
    END
  END w0_wd_in[72]
  PIN w0_wd_in[73]
    DIRECTION OUTPUT ;
    USE SIGNAL ;
    SHAPE ABUTMENT ;
    PORT
      LAYER met2 ;
      RECT 23.390 0.000 23.530 0.420 ;
    END
  END w0_wd_in[73]
  PIN w0_wd_in[74]
    DIRECTION OUTPUT ;
    USE SIGNAL ;
    SHAPE ABUTMENT ;
    PORT
      LAYER met2 ;
      RECT 25.690 0.000 25.830 0.420 ;
    END
  END w0_wd_in[74]
  PIN w0_wd_in[75]
    DIRECTION OUTPUT ;
    USE SIGNAL ;
    SHAPE ABUTMENT ;
    PORT
      LAYER met2 ;
      RECT 27.990 0.000 28.130 0.420 ;
    END
  END w0_wd_in[75]
  PIN w0_wd_in[76]
    DIRECTION OUTPUT ;
    USE SIGNAL ;
    SHAPE ABUTMENT ;
    PORT
      LAYER met2 ;
      RECT 30.290 0.000 30.430 0.420 ;
    END
  END w0_wd_in[76]
  PIN w0_wd_in[77]
    DIRECTION OUTPUT ;
    USE SIGNAL ;
    SHAPE ABUTMENT ;
    PORT
      LAYER met2 ;
      RECT 32.590 0.000 32.730 0.420 ;
    END
  END w0_wd_in[77]
  PIN w0_wd_in[78]
    DIRECTION OUTPUT ;
    USE SIGNAL ;
    SHAPE ABUTMENT ;
    PORT
      LAYER met2 ;
      RECT 34.890 0.000 35.030 0.420 ;
    END
  END w0_wd_in[78]
  PIN w0_wd_in[79]
    DIRECTION OUTPUT ;
    USE SIGNAL ;
    SHAPE ABUTMENT ;
    PORT
      LAYER met2 ;
      RECT 37.190 0.000 37.330 0.420 ;
    END
  END w0_wd_in[79]
  PIN w0_wd_in[80]
    DIRECTION OUTPUT ;
    USE SIGNAL ;
    SHAPE ABUTMENT ;
    PORT
      LAYER met2 ;
      RECT 39.490 0.000 39.630 0.420 ;
    END
  END w0_wd_in[80]
  PIN w0_wd_in[81]
    DIRECTION OUTPUT ;
    USE SIGNAL ;
    SHAPE ABUTMENT ;
    PORT
      LAYER met2 ;
      RECT 41.790 0.000 41.930 0.420 ;
    END
  END w0_wd_in[81]
  PIN w0_wd_in[82]
    DIRECTION OUTPUT ;
    USE SIGNAL ;
    SHAPE ABUTMENT ;
    PORT
      LAYER met2 ;
      RECT 44.090 0.000 44.230 0.420 ;
    END
  END w0_wd_in[82]
  PIN w0_wd_in[83]
    DIRECTION OUTPUT ;
    USE SIGNAL ;
    SHAPE ABUTMENT ;
    PORT
      LAYER met2 ;
      RECT 46.390 0.000 46.530 0.420 ;
    END
  END w0_wd_in[83]
  PIN w0_wd_in[84]
    DIRECTION OUTPUT ;
    USE SIGNAL ;
    SHAPE ABUTMENT ;
    PORT
      LAYER met2 ;
      RECT 48.690 0.000 48.830 0.420 ;
    END
  END w0_wd_in[84]
  PIN w0_wd_in[85]
    DIRECTION OUTPUT ;
    USE SIGNAL ;
    SHAPE ABUTMENT ;
    PORT
      LAYER met2 ;
      RECT 50.990 0.000 51.130 0.420 ;
    END
  END w0_wd_in[85]
  PIN w0_wd_in[86]
    DIRECTION OUTPUT ;
    USE SIGNAL ;
    SHAPE ABUTMENT ;
    PORT
      LAYER met2 ;
      RECT 53.290 0.000 53.430 0.420 ;
    END
  END w0_wd_in[86]
  PIN w0_wd_in[87]
    DIRECTION OUTPUT ;
    USE SIGNAL ;
    SHAPE ABUTMENT ;
    PORT
      LAYER met2 ;
      RECT 55.590 0.000 55.730 0.420 ;
    END
  END w0_wd_in[87]
  PIN w0_wd_in[88]
    DIRECTION OUTPUT ;
    USE SIGNAL ;
    SHAPE ABUTMENT ;
    PORT
      LAYER met2 ;
      RECT 57.890 0.000 58.030 0.420 ;
    END
  END w0_wd_in[88]
  PIN w0_wd_in[89]
    DIRECTION OUTPUT ;
    USE SIGNAL ;
    SHAPE ABUTMENT ;
    PORT
      LAYER met2 ;
      RECT 60.190 0.000 60.330 0.420 ;
    END
  END w0_wd_in[89]
  PIN w0_wd_in[90]
    DIRECTION OUTPUT ;
    USE SIGNAL ;
    SHAPE ABUTMENT ;
    PORT
      LAYER met2 ;
      RECT 62.490 0.000 62.630 0.420 ;
    END
  END w0_wd_in[90]
  PIN w0_wd_in[91]
    DIRECTION OUTPUT ;
    USE SIGNAL ;
    SHAPE ABUTMENT ;
    PORT
      LAYER met2 ;
      RECT 64.790 0.000 64.930 0.420 ;
    END
  END w0_wd_in[91]
  PIN w0_wd_in[92]
    DIRECTION OUTPUT ;
    USE SIGNAL ;
    SHAPE ABUTMENT ;
    PORT
      LAYER met2 ;
      RECT 67.090 0.000 67.230 0.420 ;
    END
  END w0_wd_in[92]
  PIN w0_wd_in[93]
    DIRECTION OUTPUT ;
    USE SIGNAL ;
    SHAPE ABUTMENT ;
    PORT
      LAYER met2 ;
      RECT 69.390 0.000 69.530 0.420 ;
    END
  END w0_wd_in[93]
  PIN w0_wd_in[94]
    DIRECTION OUTPUT ;
    USE SIGNAL ;
    SHAPE ABUTMENT ;
    PORT
      LAYER met2 ;
      RECT 71.690 0.000 71.830 0.420 ;
    END
  END w0_wd_in[94]
  PIN w0_wd_in[95]
    DIRECTION OUTPUT ;
    USE SIGNAL ;
    SHAPE ABUTMENT ;
    PORT
      LAYER met2 ;
      RECT 73.990 0.000 74.130 0.420 ;
    END
  END w0_wd_in[95]
  PIN w0_wd_in[96]
    DIRECTION OUTPUT ;
    USE SIGNAL ;
    SHAPE ABUTMENT ;
    PORT
      LAYER met2 ;
      RECT 76.290 0.000 76.430 0.420 ;
    END
  END w0_wd_in[96]
  PIN w0_wd_in[97]
    DIRECTION OUTPUT ;
    USE SIGNAL ;
    SHAPE ABUTMENT ;
    PORT
      LAYER met2 ;
      RECT 78.590 0.000 78.730 0.420 ;
    END
  END w0_wd_in[97]
  PIN w0_wd_in[98]
    DIRECTION OUTPUT ;
    USE SIGNAL ;
    SHAPE ABUTMENT ;
    PORT
      LAYER met2 ;
      RECT 80.890 0.000 81.030 0.420 ;
    END
  END w0_wd_in[98]
  PIN w0_wd_in[99]
    DIRECTION OUTPUT ;
    USE SIGNAL ;
    SHAPE ABUTMENT ;
    PORT
      LAYER met2 ;
      RECT 83.190 0.000 83.330 0.420 ;
    END
  END w0_wd_in[99]
  PIN w0_wd_in[100]
    DIRECTION OUTPUT ;
    USE SIGNAL ;
    SHAPE ABUTMENT ;
    PORT
      LAYER met2 ;
      RECT 85.490 0.000 85.630 0.420 ;
    END
  END w0_wd_in[100]
  PIN w0_wd_in[101]
    DIRECTION OUTPUT ;
    USE SIGNAL ;
    SHAPE ABUTMENT ;
    PORT
      LAYER met2 ;
      RECT 87.790 0.000 87.930 0.420 ;
    END
  END w0_wd_in[101]
  PIN w0_wd_in[102]
    DIRECTION OUTPUT ;
    USE SIGNAL ;
    SHAPE ABUTMENT ;
    PORT
      LAYER met2 ;
      RECT 90.090 0.000 90.230 0.420 ;
    END
  END w0_wd_in[102]
  PIN w0_wd_in[103]
    DIRECTION OUTPUT ;
    USE SIGNAL ;
    SHAPE ABUTMENT ;
    PORT
      LAYER met2 ;
      RECT 92.390 0.000 92.530 0.420 ;
    END
  END w0_wd_in[103]
  PIN w0_wd_in[104]
    DIRECTION OUTPUT ;
    USE SIGNAL ;
    SHAPE ABUTMENT ;
    PORT
      LAYER met2 ;
      RECT 94.690 0.000 94.830 0.420 ;
    END
  END w0_wd_in[104]
  PIN w0_wd_in[105]
    DIRECTION OUTPUT ;
    USE SIGNAL ;
    SHAPE ABUTMENT ;
    PORT
      LAYER met2 ;
      RECT 96.990 0.000 97.130 0.420 ;
    END
  END w0_wd_in[105]
  PIN w0_wd_in[106]
    DIRECTION OUTPUT ;
    USE SIGNAL ;
    SHAPE ABUTMENT ;
    PORT
      LAYER met2 ;
      RECT 99.290 0.000 99.430 0.420 ;
    END
  END w0_wd_in[106]
  PIN w0_wd_in[107]
    DIRECTION OUTPUT ;
    USE SIGNAL ;
    SHAPE ABUTMENT ;
    PORT
      LAYER met2 ;
      RECT 101.590 0.000 101.730 0.420 ;
    END
  END w0_wd_in[107]
  PIN w0_wd_in[108]
    DIRECTION OUTPUT ;
    USE SIGNAL ;
    SHAPE ABUTMENT ;
    PORT
      LAYER met2 ;
      RECT 103.890 0.000 104.030 0.420 ;
    END
  END w0_wd_in[108]
  PIN w0_wd_in[109]
    DIRECTION OUTPUT ;
    USE SIGNAL ;
    SHAPE ABUTMENT ;
    PORT
      LAYER met2 ;
      RECT 106.190 0.000 106.330 0.420 ;
    END
  END w0_wd_in[109]
  PIN w0_wd_in[110]
    DIRECTION OUTPUT ;
    USE SIGNAL ;
    SHAPE ABUTMENT ;
    PORT
      LAYER met2 ;
      RECT 108.490 0.000 108.630 0.420 ;
    END
  END w0_wd_in[110]
  PIN w0_wd_in[111]
    DIRECTION OUTPUT ;
    USE SIGNAL ;
    SHAPE ABUTMENT ;
    PORT
      LAYER met2 ;
      RECT 110.790 0.000 110.930 0.420 ;
    END
  END w0_wd_in[111]
  PIN w0_wd_in[112]
    DIRECTION OUTPUT ;
    USE SIGNAL ;
    SHAPE ABUTMENT ;
    PORT
      LAYER met2 ;
      RECT 113.090 0.000 113.230 0.420 ;
    END
  END w0_wd_in[112]
  PIN w0_wd_in[113]
    DIRECTION OUTPUT ;
    USE SIGNAL ;
    SHAPE ABUTMENT ;
    PORT
      LAYER met2 ;
      RECT 115.390 0.000 115.530 0.420 ;
    END
  END w0_wd_in[113]
  PIN w0_wd_in[114]
    DIRECTION OUTPUT ;
    USE SIGNAL ;
    SHAPE ABUTMENT ;
    PORT
      LAYER met2 ;
      RECT 117.690 0.000 117.830 0.420 ;
    END
  END w0_wd_in[114]
  PIN w0_wd_in[115]
    DIRECTION OUTPUT ;
    USE SIGNAL ;
    SHAPE ABUTMENT ;
    PORT
      LAYER met2 ;
      RECT 119.990 0.000 120.130 0.420 ;
    END
  END w0_wd_in[115]
  PIN w0_wd_in[116]
    DIRECTION OUTPUT ;
    USE SIGNAL ;
    SHAPE ABUTMENT ;
    PORT
      LAYER met2 ;
      RECT 122.290 0.000 122.430 0.420 ;
    END
  END w0_wd_in[116]
  PIN w0_wd_in[117]
    DIRECTION OUTPUT ;
    USE SIGNAL ;
    SHAPE ABUTMENT ;
    PORT
      LAYER met2 ;
      RECT 124.590 0.000 124.730 0.420 ;
    END
  END w0_wd_in[117]
  PIN w0_wd_in[118]
    DIRECTION OUTPUT ;
    USE SIGNAL ;
    SHAPE ABUTMENT ;
    PORT
      LAYER met2 ;
      RECT 126.890 0.000 127.030 0.420 ;
    END
  END w0_wd_in[118]
  PIN w0_wd_in[119]
    DIRECTION OUTPUT ;
    USE SIGNAL ;
    SHAPE ABUTMENT ;
    PORT
      LAYER met2 ;
      RECT 129.190 0.000 129.330 0.420 ;
    END
  END w0_wd_in[119]
  PIN w0_wd_in[120]
    DIRECTION OUTPUT ;
    USE SIGNAL ;
    SHAPE ABUTMENT ;
    PORT
      LAYER met2 ;
      RECT 131.490 0.000 131.630 0.420 ;
    END
  END w0_wd_in[120]
  PIN w0_wd_in[121]
    DIRECTION OUTPUT ;
    USE SIGNAL ;
    SHAPE ABUTMENT ;
    PORT
      LAYER met2 ;
      RECT 133.790 0.000 133.930 0.420 ;
    END
  END w0_wd_in[121]
  PIN w0_wd_in[122]
    DIRECTION OUTPUT ;
    USE SIGNAL ;
    SHAPE ABUTMENT ;
    PORT
      LAYER met2 ;
      RECT 136.090 0.000 136.230 0.420 ;
    END
  END w0_wd_in[122]
  PIN w0_wd_in[123]
    DIRECTION OUTPUT ;
    USE SIGNAL ;
    SHAPE ABUTMENT ;
    PORT
      LAYER met2 ;
      RECT 138.390 0.000 138.530 0.420 ;
    END
  END w0_wd_in[123]
  PIN w0_wd_in[124]
    DIRECTION OUTPUT ;
    USE SIGNAL ;
    SHAPE ABUTMENT ;
    PORT
      LAYER met2 ;
      RECT 140.690 0.000 140.830 0.420 ;
    END
  END w0_wd_in[124]
  PIN w0_wd_in[125]
    DIRECTION OUTPUT ;
    USE SIGNAL ;
    SHAPE ABUTMENT ;
    PORT
      LAYER met2 ;
      RECT 142.990 0.000 143.130 0.420 ;
    END
  END w0_wd_in[125]
  PIN w0_wd_in[126]
    DIRECTION OUTPUT ;
    USE SIGNAL ;
    SHAPE ABUTMENT ;
    PORT
      LAYER met2 ;
      RECT 145.290 0.000 145.430 0.420 ;
    END
  END w0_wd_in[126]
  PIN w0_wd_in[127]
    DIRECTION OUTPUT ;
    USE SIGNAL ;
    SHAPE ABUTMENT ;
    PORT
      LAYER met2 ;
      RECT 147.590 0.000 147.730 0.420 ;
    END
  END w0_wd_in[127]
  PIN r0_rd_out[0]
    DIRECTION OUTPUT ;
    USE SIGNAL ;
    SHAPE ABUTMENT ;
    PORT
      LAYER met2 ;
      RECT 149.890 0.000 150.030 0.420 ;
    END
  END r0_rd_out[0]
  PIN r0_rd_out[1]
    DIRECTION OUTPUT ;
    USE SIGNAL ;
    SHAPE ABUTMENT ;
    PORT
      LAYER met2 ;
      RECT 152.190 0.000 152.330 0.420 ;
    END
  END r0_rd_out[1]
  PIN r0_rd_out[2]
    DIRECTION OUTPUT ;
    USE SIGNAL ;
    SHAPE ABUTMENT ;
    PORT
      LAYER met2 ;
      RECT 154.490 0.000 154.630 0.420 ;
    END
  END r0_rd_out[2]
  PIN r0_rd_out[3]
    DIRECTION OUTPUT ;
    USE SIGNAL ;
    SHAPE ABUTMENT ;
    PORT
      LAYER met2 ;
      RECT 156.790 0.000 156.930 0.420 ;
    END
  END r0_rd_out[3]
  PIN r0_rd_out[4]
    DIRECTION OUTPUT ;
    USE SIGNAL ;
    SHAPE ABUTMENT ;
    PORT
      LAYER met2 ;
      RECT 159.090 0.000 159.230 0.420 ;
    END
  END r0_rd_out[4]
  PIN r0_rd_out[5]
    DIRECTION OUTPUT ;
    USE SIGNAL ;
    SHAPE ABUTMENT ;
    PORT
      LAYER met2 ;
      RECT 161.390 0.000 161.530 0.420 ;
    END
  END r0_rd_out[5]
  PIN r0_rd_out[6]
    DIRECTION OUTPUT ;
    USE SIGNAL ;
    SHAPE ABUTMENT ;
    PORT
      LAYER met2 ;
      RECT 163.690 0.000 163.830 0.420 ;
    END
  END r0_rd_out[6]
  PIN r0_rd_out[7]
    DIRECTION OUTPUT ;
    USE SIGNAL ;
    SHAPE ABUTMENT ;
    PORT
      LAYER met2 ;
      RECT 165.990 0.000 166.130 0.420 ;
    END
  END r0_rd_out[7]
  PIN r0_rd_out[8]
    DIRECTION OUTPUT ;
    USE SIGNAL ;
    SHAPE ABUTMENT ;
    PORT
      LAYER met2 ;
      RECT 168.290 0.000 168.430 0.420 ;
    END
  END r0_rd_out[8]
  PIN r0_rd_out[9]
    DIRECTION OUTPUT ;
    USE SIGNAL ;
    SHAPE ABUTMENT ;
    PORT
      LAYER met2 ;
      RECT 170.590 0.000 170.730 0.420 ;
    END
  END r0_rd_out[9]
  PIN r0_rd_out[10]
    DIRECTION OUTPUT ;
    USE SIGNAL ;
    SHAPE ABUTMENT ;
    PORT
      LAYER met2 ;
      RECT 172.890 0.000 173.030 0.420 ;
    END
  END r0_rd_out[10]
  PIN r0_rd_out[11]
    DIRECTION OUTPUT ;
    USE SIGNAL ;
    SHAPE ABUTMENT ;
    PORT
      LAYER met2 ;
      RECT 175.190 0.000 175.330 0.420 ;
    END
  END r0_rd_out[11]
  PIN r0_rd_out[12]
    DIRECTION OUTPUT ;
    USE SIGNAL ;
    SHAPE ABUTMENT ;
    PORT
      LAYER met2 ;
      RECT 177.490 0.000 177.630 0.420 ;
    END
  END r0_rd_out[12]
  PIN r0_rd_out[13]
    DIRECTION OUTPUT ;
    USE SIGNAL ;
    SHAPE ABUTMENT ;
    PORT
      LAYER met2 ;
      RECT 179.790 0.000 179.930 0.420 ;
    END
  END r0_rd_out[13]
  PIN r0_rd_out[14]
    DIRECTION OUTPUT ;
    USE SIGNAL ;
    SHAPE ABUTMENT ;
    PORT
      LAYER met2 ;
      RECT 182.090 0.000 182.230 0.420 ;
    END
  END r0_rd_out[14]
  PIN r0_rd_out[15]
    DIRECTION OUTPUT ;
    USE SIGNAL ;
    SHAPE ABUTMENT ;
    PORT
      LAYER met2 ;
      RECT 184.390 0.000 184.530 0.420 ;
    END
  END r0_rd_out[15]
  PIN r0_rd_out[16]
    DIRECTION OUTPUT ;
    USE SIGNAL ;
    SHAPE ABUTMENT ;
    PORT
      LAYER met2 ;
      RECT 186.690 0.000 186.830 0.420 ;
    END
  END r0_rd_out[16]
  PIN r0_rd_out[17]
    DIRECTION OUTPUT ;
    USE SIGNAL ;
    SHAPE ABUTMENT ;
    PORT
      LAYER met2 ;
      RECT 188.990 0.000 189.130 0.420 ;
    END
  END r0_rd_out[17]
  PIN r0_rd_out[18]
    DIRECTION OUTPUT ;
    USE SIGNAL ;
    SHAPE ABUTMENT ;
    PORT
      LAYER met2 ;
      RECT 191.290 0.000 191.430 0.420 ;
    END
  END r0_rd_out[18]
  PIN r0_rd_out[19]
    DIRECTION OUTPUT ;
    USE SIGNAL ;
    SHAPE ABUTMENT ;
    PORT
      LAYER met2 ;
      RECT 193.590 0.000 193.730 0.420 ;
    END
  END r0_rd_out[19]
  PIN r0_rd_out[20]
    DIRECTION OUTPUT ;
    USE SIGNAL ;
    SHAPE ABUTMENT ;
    PORT
      LAYER met2 ;
      RECT 195.890 0.000 196.030 0.420 ;
    END
  END r0_rd_out[20]
  PIN r0_rd_out[21]
    DIRECTION OUTPUT ;
    USE SIGNAL ;
    SHAPE ABUTMENT ;
    PORT
      LAYER met2 ;
      RECT 198.190 0.000 198.330 0.420 ;
    END
  END r0_rd_out[21]
  PIN r0_rd_out[22]
    DIRECTION OUTPUT ;
    USE SIGNAL ;
    SHAPE ABUTMENT ;
    PORT
      LAYER met2 ;
      RECT 200.490 0.000 200.630 0.420 ;
    END
  END r0_rd_out[22]
  PIN r0_rd_out[23]
    DIRECTION OUTPUT ;
    USE SIGNAL ;
    SHAPE ABUTMENT ;
    PORT
      LAYER met2 ;
      RECT 202.790 0.000 202.930 0.420 ;
    END
  END r0_rd_out[23]
  PIN r0_rd_out[24]
    DIRECTION OUTPUT ;
    USE SIGNAL ;
    SHAPE ABUTMENT ;
    PORT
      LAYER met2 ;
      RECT 205.090 0.000 205.230 0.420 ;
    END
  END r0_rd_out[24]
  PIN r0_rd_out[25]
    DIRECTION OUTPUT ;
    USE SIGNAL ;
    SHAPE ABUTMENT ;
    PORT
      LAYER met2 ;
      RECT 207.390 0.000 207.530 0.420 ;
    END
  END r0_rd_out[25]
  PIN r0_rd_out[26]
    DIRECTION OUTPUT ;
    USE SIGNAL ;
    SHAPE ABUTMENT ;
    PORT
      LAYER met2 ;
      RECT 209.690 0.000 209.830 0.420 ;
    END
  END r0_rd_out[26]
  PIN r0_rd_out[27]
    DIRECTION OUTPUT ;
    USE SIGNAL ;
    SHAPE ABUTMENT ;
    PORT
      LAYER met2 ;
      RECT 211.990 0.000 212.130 0.420 ;
    END
  END r0_rd_out[27]
  PIN r0_rd_out[28]
    DIRECTION OUTPUT ;
    USE SIGNAL ;
    SHAPE ABUTMENT ;
    PORT
      LAYER met2 ;
      RECT 214.290 0.000 214.430 0.420 ;
    END
  END r0_rd_out[28]
  PIN r0_rd_out[29]
    DIRECTION OUTPUT ;
    USE SIGNAL ;
    SHAPE ABUTMENT ;
    PORT
      LAYER met2 ;
      RECT 216.590 0.000 216.730 0.420 ;
    END
  END r0_rd_out[29]
  PIN r0_rd_out[30]
    DIRECTION OUTPUT ;
    USE SIGNAL ;
    SHAPE ABUTMENT ;
    PORT
      LAYER met2 ;
      RECT 218.890 0.000 219.030 0.420 ;
    END
  END r0_rd_out[30]
  PIN r0_rd_out[31]
    DIRECTION OUTPUT ;
    USE SIGNAL ;
    SHAPE ABUTMENT ;
    PORT
      LAYER met2 ;
      RECT 221.190 0.000 221.330 0.420 ;
    END
  END r0_rd_out[31]
  PIN r0_rd_out[32]
    DIRECTION OUTPUT ;
    USE SIGNAL ;
    SHAPE ABUTMENT ;
    PORT
      LAYER met2 ;
      RECT 223.490 0.000 223.630 0.420 ;
    END
  END r0_rd_out[32]
  PIN r0_rd_out[33]
    DIRECTION OUTPUT ;
    USE SIGNAL ;
    SHAPE ABUTMENT ;
    PORT
      LAYER met2 ;
      RECT 225.790 0.000 225.930 0.420 ;
    END
  END r0_rd_out[33]
  PIN r0_rd_out[34]
    DIRECTION OUTPUT ;
    USE SIGNAL ;
    SHAPE ABUTMENT ;
    PORT
      LAYER met2 ;
      RECT 228.090 0.000 228.230 0.420 ;
    END
  END r0_rd_out[34]
  PIN r0_rd_out[35]
    DIRECTION OUTPUT ;
    USE SIGNAL ;
    SHAPE ABUTMENT ;
    PORT
      LAYER met2 ;
      RECT 230.390 0.000 230.530 0.420 ;
    END
  END r0_rd_out[35]
  PIN r0_rd_out[36]
    DIRECTION OUTPUT ;
    USE SIGNAL ;
    SHAPE ABUTMENT ;
    PORT
      LAYER met2 ;
      RECT 232.690 0.000 232.830 0.420 ;
    END
  END r0_rd_out[36]
  PIN r0_rd_out[37]
    DIRECTION OUTPUT ;
    USE SIGNAL ;
    SHAPE ABUTMENT ;
    PORT
      LAYER met2 ;
      RECT 234.990 0.000 235.130 0.420 ;
    END
  END r0_rd_out[37]
  PIN r0_rd_out[38]
    DIRECTION OUTPUT ;
    USE SIGNAL ;
    SHAPE ABUTMENT ;
    PORT
      LAYER met2 ;
      RECT 237.290 0.000 237.430 0.420 ;
    END
  END r0_rd_out[38]
  PIN r0_rd_out[39]
    DIRECTION OUTPUT ;
    USE SIGNAL ;
    SHAPE ABUTMENT ;
    PORT
      LAYER met2 ;
      RECT 239.590 0.000 239.730 0.420 ;
    END
  END r0_rd_out[39]
  PIN r0_rd_out[40]
    DIRECTION OUTPUT ;
    USE SIGNAL ;
    SHAPE ABUTMENT ;
    PORT
      LAYER met2 ;
      RECT 241.890 0.000 242.030 0.420 ;
    END
  END r0_rd_out[40]
  PIN r0_rd_out[41]
    DIRECTION OUTPUT ;
    USE SIGNAL ;
    SHAPE ABUTMENT ;
    PORT
      LAYER met2 ;
      RECT 244.190 0.000 244.330 0.420 ;
    END
  END r0_rd_out[41]
  PIN r0_rd_out[42]
    DIRECTION OUTPUT ;
    USE SIGNAL ;
    SHAPE ABUTMENT ;
    PORT
      LAYER met2 ;
      RECT 246.490 0.000 246.630 0.420 ;
    END
  END r0_rd_out[42]
  PIN r0_rd_out[43]
    DIRECTION OUTPUT ;
    USE SIGNAL ;
    SHAPE ABUTMENT ;
    PORT
      LAYER met2 ;
      RECT 248.790 0.000 248.930 0.420 ;
    END
  END r0_rd_out[43]
  PIN r0_rd_out[44]
    DIRECTION OUTPUT ;
    USE SIGNAL ;
    SHAPE ABUTMENT ;
    PORT
      LAYER met2 ;
      RECT 251.090 0.000 251.230 0.420 ;
    END
  END r0_rd_out[44]
  PIN r0_rd_out[45]
    DIRECTION OUTPUT ;
    USE SIGNAL ;
    SHAPE ABUTMENT ;
    PORT
      LAYER met2 ;
      RECT 253.390 0.000 253.530 0.420 ;
    END
  END r0_rd_out[45]
  PIN r0_rd_out[46]
    DIRECTION OUTPUT ;
    USE SIGNAL ;
    SHAPE ABUTMENT ;
    PORT
      LAYER met2 ;
      RECT 255.690 0.000 255.830 0.420 ;
    END
  END r0_rd_out[46]
  PIN r0_rd_out[47]
    DIRECTION OUTPUT ;
    USE SIGNAL ;
    SHAPE ABUTMENT ;
    PORT
      LAYER met2 ;
      RECT 257.990 0.000 258.130 0.420 ;
    END
  END r0_rd_out[47]
  PIN r0_rd_out[48]
    DIRECTION OUTPUT ;
    USE SIGNAL ;
    SHAPE ABUTMENT ;
    PORT
      LAYER met2 ;
      RECT 260.290 0.000 260.430 0.420 ;
    END
  END r0_rd_out[48]
  PIN r0_rd_out[49]
    DIRECTION OUTPUT ;
    USE SIGNAL ;
    SHAPE ABUTMENT ;
    PORT
      LAYER met2 ;
      RECT 262.590 0.000 262.730 0.420 ;
    END
  END r0_rd_out[49]
  PIN r0_rd_out[50]
    DIRECTION OUTPUT ;
    USE SIGNAL ;
    SHAPE ABUTMENT ;
    PORT
      LAYER met2 ;
      RECT 264.890 0.000 265.030 0.420 ;
    END
  END r0_rd_out[50]
  PIN r0_rd_out[51]
    DIRECTION OUTPUT ;
    USE SIGNAL ;
    SHAPE ABUTMENT ;
    PORT
      LAYER met2 ;
      RECT 267.190 0.000 267.330 0.420 ;
    END
  END r0_rd_out[51]
  PIN r0_rd_out[52]
    DIRECTION OUTPUT ;
    USE SIGNAL ;
    SHAPE ABUTMENT ;
    PORT
      LAYER met2 ;
      RECT 269.490 0.000 269.630 0.420 ;
    END
  END r0_rd_out[52]
  PIN r0_rd_out[53]
    DIRECTION OUTPUT ;
    USE SIGNAL ;
    SHAPE ABUTMENT ;
    PORT
      LAYER met2 ;
      RECT 271.790 0.000 271.930 0.420 ;
    END
  END r0_rd_out[53]
  PIN r0_rd_out[54]
    DIRECTION OUTPUT ;
    USE SIGNAL ;
    SHAPE ABUTMENT ;
    PORT
      LAYER met2 ;
      RECT 274.090 0.000 274.230 0.420 ;
    END
  END r0_rd_out[54]
  PIN r0_rd_out[55]
    DIRECTION OUTPUT ;
    USE SIGNAL ;
    SHAPE ABUTMENT ;
    PORT
      LAYER met2 ;
      RECT 276.390 0.000 276.530 0.420 ;
    END
  END r0_rd_out[55]
  PIN r0_rd_out[56]
    DIRECTION OUTPUT ;
    USE SIGNAL ;
    SHAPE ABUTMENT ;
    PORT
      LAYER met2 ;
      RECT 278.690 0.000 278.830 0.420 ;
    END
  END r0_rd_out[56]
  PIN r0_rd_out[57]
    DIRECTION OUTPUT ;
    USE SIGNAL ;
    SHAPE ABUTMENT ;
    PORT
      LAYER met2 ;
      RECT 280.990 0.000 281.130 0.420 ;
    END
  END r0_rd_out[57]
  PIN r0_rd_out[58]
    DIRECTION OUTPUT ;
    USE SIGNAL ;
    SHAPE ABUTMENT ;
    PORT
      LAYER met2 ;
      RECT 283.290 0.000 283.430 0.420 ;
    END
  END r0_rd_out[58]
  PIN r0_rd_out[59]
    DIRECTION OUTPUT ;
    USE SIGNAL ;
    SHAPE ABUTMENT ;
    PORT
      LAYER met2 ;
      RECT 285.590 0.000 285.730 0.420 ;
    END
  END r0_rd_out[59]
  PIN r0_rd_out[60]
    DIRECTION OUTPUT ;
    USE SIGNAL ;
    SHAPE ABUTMENT ;
    PORT
      LAYER met2 ;
      RECT 287.890 0.000 288.030 0.420 ;
    END
  END r0_rd_out[60]
  PIN r0_rd_out[61]
    DIRECTION OUTPUT ;
    USE SIGNAL ;
    SHAPE ABUTMENT ;
    PORT
      LAYER met2 ;
      RECT 290.190 0.000 290.330 0.420 ;
    END
  END r0_rd_out[61]
  PIN r0_rd_out[62]
    DIRECTION OUTPUT ;
    USE SIGNAL ;
    SHAPE ABUTMENT ;
    PORT
      LAYER met2 ;
      RECT 292.490 0.000 292.630 0.420 ;
    END
  END r0_rd_out[62]
  PIN r0_rd_out[63]
    DIRECTION OUTPUT ;
    USE SIGNAL ;
    SHAPE ABUTMENT ;
    PORT
      LAYER met2 ;
      RECT 294.790 0.000 294.930 0.420 ;
    END
  END r0_rd_out[63]
  PIN r0_rd_out[64]
    DIRECTION OUTPUT ;
    USE SIGNAL ;
    SHAPE ABUTMENT ;
    PORT
      LAYER met2 ;
      RECT 149.890 489.180 150.030 489.600 ;
    END
  END r0_rd_out[64]
  PIN r0_rd_out[65]
    DIRECTION OUTPUT ;
    USE SIGNAL ;
    SHAPE ABUTMENT ;
    PORT
      LAYER met2 ;
      RECT 152.190 489.180 152.330 489.600 ;
    END
  END r0_rd_out[65]
  PIN r0_rd_out[66]
    DIRECTION OUTPUT ;
    USE SIGNAL ;
    SHAPE ABUTMENT ;
    PORT
      LAYER met2 ;
      RECT 154.490 489.180 154.630 489.600 ;
    END
  END r0_rd_out[66]
  PIN r0_rd_out[67]
    DIRECTION OUTPUT ;
    USE SIGNAL ;
    SHAPE ABUTMENT ;
    PORT
      LAYER met2 ;
      RECT 156.790 489.180 156.930 489.600 ;
    END
  END r0_rd_out[67]
  PIN r0_rd_out[68]
    DIRECTION OUTPUT ;
    USE SIGNAL ;
    SHAPE ABUTMENT ;
    PORT
      LAYER met2 ;
      RECT 159.090 489.180 159.230 489.600 ;
    END
  END r0_rd_out[68]
  PIN r0_rd_out[69]
    DIRECTION OUTPUT ;
    USE SIGNAL ;
    SHAPE ABUTMENT ;
    PORT
      LAYER met2 ;
      RECT 161.390 489.180 161.530 489.600 ;
    END
  END r0_rd_out[69]
  PIN r0_rd_out[70]
    DIRECTION OUTPUT ;
    USE SIGNAL ;
    SHAPE ABUTMENT ;
    PORT
      LAYER met2 ;
      RECT 163.690 489.180 163.830 489.600 ;
    END
  END r0_rd_out[70]
  PIN r0_rd_out[71]
    DIRECTION OUTPUT ;
    USE SIGNAL ;
    SHAPE ABUTMENT ;
    PORT
      LAYER met2 ;
      RECT 165.990 489.180 166.130 489.600 ;
    END
  END r0_rd_out[71]
  PIN r0_rd_out[72]
    DIRECTION OUTPUT ;
    USE SIGNAL ;
    SHAPE ABUTMENT ;
    PORT
      LAYER met2 ;
      RECT 168.290 489.180 168.430 489.600 ;
    END
  END r0_rd_out[72]
  PIN r0_rd_out[73]
    DIRECTION OUTPUT ;
    USE SIGNAL ;
    SHAPE ABUTMENT ;
    PORT
      LAYER met2 ;
      RECT 170.590 489.180 170.730 489.600 ;
    END
  END r0_rd_out[73]
  PIN r0_rd_out[74]
    DIRECTION OUTPUT ;
    USE SIGNAL ;
    SHAPE ABUTMENT ;
    PORT
      LAYER met2 ;
      RECT 172.890 489.180 173.030 489.600 ;
    END
  END r0_rd_out[74]
  PIN r0_rd_out[75]
    DIRECTION OUTPUT ;
    USE SIGNAL ;
    SHAPE ABUTMENT ;
    PORT
      LAYER met2 ;
      RECT 175.190 489.180 175.330 489.600 ;
    END
  END r0_rd_out[75]
  PIN r0_rd_out[76]
    DIRECTION OUTPUT ;
    USE SIGNAL ;
    SHAPE ABUTMENT ;
    PORT
      LAYER met2 ;
      RECT 177.490 489.180 177.630 489.600 ;
    END
  END r0_rd_out[76]
  PIN r0_rd_out[77]
    DIRECTION OUTPUT ;
    USE SIGNAL ;
    SHAPE ABUTMENT ;
    PORT
      LAYER met2 ;
      RECT 179.790 489.180 179.930 489.600 ;
    END
  END r0_rd_out[77]
  PIN r0_rd_out[78]
    DIRECTION OUTPUT ;
    USE SIGNAL ;
    SHAPE ABUTMENT ;
    PORT
      LAYER met2 ;
      RECT 182.090 489.180 182.230 489.600 ;
    END
  END r0_rd_out[78]
  PIN r0_rd_out[79]
    DIRECTION OUTPUT ;
    USE SIGNAL ;
    SHAPE ABUTMENT ;
    PORT
      LAYER met2 ;
      RECT 184.390 489.180 184.530 489.600 ;
    END
  END r0_rd_out[79]
  PIN r0_rd_out[80]
    DIRECTION OUTPUT ;
    USE SIGNAL ;
    SHAPE ABUTMENT ;
    PORT
      LAYER met2 ;
      RECT 186.690 489.180 186.830 489.600 ;
    END
  END r0_rd_out[80]
  PIN r0_rd_out[81]
    DIRECTION OUTPUT ;
    USE SIGNAL ;
    SHAPE ABUTMENT ;
    PORT
      LAYER met2 ;
      RECT 188.990 489.180 189.130 489.600 ;
    END
  END r0_rd_out[81]
  PIN r0_rd_out[82]
    DIRECTION OUTPUT ;
    USE SIGNAL ;
    SHAPE ABUTMENT ;
    PORT
      LAYER met2 ;
      RECT 191.290 489.180 191.430 489.600 ;
    END
  END r0_rd_out[82]
  PIN r0_rd_out[83]
    DIRECTION OUTPUT ;
    USE SIGNAL ;
    SHAPE ABUTMENT ;
    PORT
      LAYER met2 ;
      RECT 193.590 489.180 193.730 489.600 ;
    END
  END r0_rd_out[83]
  PIN r0_rd_out[84]
    DIRECTION OUTPUT ;
    USE SIGNAL ;
    SHAPE ABUTMENT ;
    PORT
      LAYER met2 ;
      RECT 195.890 489.180 196.030 489.600 ;
    END
  END r0_rd_out[84]
  PIN r0_rd_out[85]
    DIRECTION OUTPUT ;
    USE SIGNAL ;
    SHAPE ABUTMENT ;
    PORT
      LAYER met2 ;
      RECT 198.190 489.180 198.330 489.600 ;
    END
  END r0_rd_out[85]
  PIN r0_rd_out[86]
    DIRECTION OUTPUT ;
    USE SIGNAL ;
    SHAPE ABUTMENT ;
    PORT
      LAYER met2 ;
      RECT 200.490 489.180 200.630 489.600 ;
    END
  END r0_rd_out[86]
  PIN r0_rd_out[87]
    DIRECTION OUTPUT ;
    USE SIGNAL ;
    SHAPE ABUTMENT ;
    PORT
      LAYER met2 ;
      RECT 202.790 489.180 202.930 489.600 ;
    END
  END r0_rd_out[87]
  PIN r0_rd_out[88]
    DIRECTION OUTPUT ;
    USE SIGNAL ;
    SHAPE ABUTMENT ;
    PORT
      LAYER met2 ;
      RECT 205.090 489.180 205.230 489.600 ;
    END
  END r0_rd_out[88]
  PIN r0_rd_out[89]
    DIRECTION OUTPUT ;
    USE SIGNAL ;
    SHAPE ABUTMENT ;
    PORT
      LAYER met2 ;
      RECT 207.390 489.180 207.530 489.600 ;
    END
  END r0_rd_out[89]
  PIN r0_rd_out[90]
    DIRECTION OUTPUT ;
    USE SIGNAL ;
    SHAPE ABUTMENT ;
    PORT
      LAYER met2 ;
      RECT 209.690 489.180 209.830 489.600 ;
    END
  END r0_rd_out[90]
  PIN r0_rd_out[91]
    DIRECTION OUTPUT ;
    USE SIGNAL ;
    SHAPE ABUTMENT ;
    PORT
      LAYER met2 ;
      RECT 211.990 489.180 212.130 489.600 ;
    END
  END r0_rd_out[91]
  PIN r0_rd_out[92]
    DIRECTION OUTPUT ;
    USE SIGNAL ;
    SHAPE ABUTMENT ;
    PORT
      LAYER met2 ;
      RECT 214.290 489.180 214.430 489.600 ;
    END
  END r0_rd_out[92]
  PIN r0_rd_out[93]
    DIRECTION OUTPUT ;
    USE SIGNAL ;
    SHAPE ABUTMENT ;
    PORT
      LAYER met2 ;
      RECT 216.590 489.180 216.730 489.600 ;
    END
  END r0_rd_out[93]
  PIN r0_rd_out[94]
    DIRECTION OUTPUT ;
    USE SIGNAL ;
    SHAPE ABUTMENT ;
    PORT
      LAYER met2 ;
      RECT 218.890 489.180 219.030 489.600 ;
    END
  END r0_rd_out[94]
  PIN r0_rd_out[95]
    DIRECTION OUTPUT ;
    USE SIGNAL ;
    SHAPE ABUTMENT ;
    PORT
      LAYER met2 ;
      RECT 221.190 489.180 221.330 489.600 ;
    END
  END r0_rd_out[95]
  PIN r0_rd_out[96]
    DIRECTION OUTPUT ;
    USE SIGNAL ;
    SHAPE ABUTMENT ;
    PORT
      LAYER met2 ;
      RECT 223.490 489.180 223.630 489.600 ;
    END
  END r0_rd_out[96]
  PIN r0_rd_out[97]
    DIRECTION OUTPUT ;
    USE SIGNAL ;
    SHAPE ABUTMENT ;
    PORT
      LAYER met2 ;
      RECT 225.790 489.180 225.930 489.600 ;
    END
  END r0_rd_out[97]
  PIN r0_rd_out[98]
    DIRECTION OUTPUT ;
    USE SIGNAL ;
    SHAPE ABUTMENT ;
    PORT
      LAYER met2 ;
      RECT 228.090 489.180 228.230 489.600 ;
    END
  END r0_rd_out[98]
  PIN r0_rd_out[99]
    DIRECTION OUTPUT ;
    USE SIGNAL ;
    SHAPE ABUTMENT ;
    PORT
      LAYER met2 ;
      RECT 230.390 489.180 230.530 489.600 ;
    END
  END r0_rd_out[99]
  PIN r0_rd_out[100]
    DIRECTION OUTPUT ;
    USE SIGNAL ;
    SHAPE ABUTMENT ;
    PORT
      LAYER met2 ;
      RECT 232.690 489.180 232.830 489.600 ;
    END
  END r0_rd_out[100]
  PIN r0_rd_out[101]
    DIRECTION OUTPUT ;
    USE SIGNAL ;
    SHAPE ABUTMENT ;
    PORT
      LAYER met2 ;
      RECT 234.990 489.180 235.130 489.600 ;
    END
  END r0_rd_out[101]
  PIN r0_rd_out[102]
    DIRECTION OUTPUT ;
    USE SIGNAL ;
    SHAPE ABUTMENT ;
    PORT
      LAYER met2 ;
      RECT 237.290 489.180 237.430 489.600 ;
    END
  END r0_rd_out[102]
  PIN r0_rd_out[103]
    DIRECTION OUTPUT ;
    USE SIGNAL ;
    SHAPE ABUTMENT ;
    PORT
      LAYER met2 ;
      RECT 239.590 489.180 239.730 489.600 ;
    END
  END r0_rd_out[103]
  PIN r0_rd_out[104]
    DIRECTION OUTPUT ;
    USE SIGNAL ;
    SHAPE ABUTMENT ;
    PORT
      LAYER met2 ;
      RECT 241.890 489.180 242.030 489.600 ;
    END
  END r0_rd_out[104]
  PIN r0_rd_out[105]
    DIRECTION OUTPUT ;
    USE SIGNAL ;
    SHAPE ABUTMENT ;
    PORT
      LAYER met2 ;
      RECT 244.190 489.180 244.330 489.600 ;
    END
  END r0_rd_out[105]
  PIN r0_rd_out[106]
    DIRECTION OUTPUT ;
    USE SIGNAL ;
    SHAPE ABUTMENT ;
    PORT
      LAYER met2 ;
      RECT 246.490 489.180 246.630 489.600 ;
    END
  END r0_rd_out[106]
  PIN r0_rd_out[107]
    DIRECTION OUTPUT ;
    USE SIGNAL ;
    SHAPE ABUTMENT ;
    PORT
      LAYER met2 ;
      RECT 248.790 489.180 248.930 489.600 ;
    END
  END r0_rd_out[107]
  PIN r0_rd_out[108]
    DIRECTION OUTPUT ;
    USE SIGNAL ;
    SHAPE ABUTMENT ;
    PORT
      LAYER met2 ;
      RECT 251.090 489.180 251.230 489.600 ;
    END
  END r0_rd_out[108]
  PIN r0_rd_out[109]
    DIRECTION OUTPUT ;
    USE SIGNAL ;
    SHAPE ABUTMENT ;
    PORT
      LAYER met2 ;
      RECT 253.390 489.180 253.530 489.600 ;
    END
  END r0_rd_out[109]
  PIN r0_rd_out[110]
    DIRECTION OUTPUT ;
    USE SIGNAL ;
    SHAPE ABUTMENT ;
    PORT
      LAYER met2 ;
      RECT 255.690 489.180 255.830 489.600 ;
    END
  END r0_rd_out[110]
  PIN r0_rd_out[111]
    DIRECTION OUTPUT ;
    USE SIGNAL ;
    SHAPE ABUTMENT ;
    PORT
      LAYER met2 ;
      RECT 257.990 489.180 258.130 489.600 ;
    END
  END r0_rd_out[111]
  PIN r0_rd_out[112]
    DIRECTION OUTPUT ;
    USE SIGNAL ;
    SHAPE ABUTMENT ;
    PORT
      LAYER met2 ;
      RECT 260.290 489.180 260.430 489.600 ;
    END
  END r0_rd_out[112]
  PIN r0_rd_out[113]
    DIRECTION OUTPUT ;
    USE SIGNAL ;
    SHAPE ABUTMENT ;
    PORT
      LAYER met2 ;
      RECT 262.590 489.180 262.730 489.600 ;
    END
  END r0_rd_out[113]
  PIN r0_rd_out[114]
    DIRECTION OUTPUT ;
    USE SIGNAL ;
    SHAPE ABUTMENT ;
    PORT
      LAYER met2 ;
      RECT 264.890 489.180 265.030 489.600 ;
    END
  END r0_rd_out[114]
  PIN r0_rd_out[115]
    DIRECTION OUTPUT ;
    USE SIGNAL ;
    SHAPE ABUTMENT ;
    PORT
      LAYER met2 ;
      RECT 267.190 489.180 267.330 489.600 ;
    END
  END r0_rd_out[115]
  PIN r0_rd_out[116]
    DIRECTION OUTPUT ;
    USE SIGNAL ;
    SHAPE ABUTMENT ;
    PORT
      LAYER met2 ;
      RECT 269.490 489.180 269.630 489.600 ;
    END
  END r0_rd_out[116]
  PIN r0_rd_out[117]
    DIRECTION OUTPUT ;
    USE SIGNAL ;
    SHAPE ABUTMENT ;
    PORT
      LAYER met2 ;
      RECT 271.790 489.180 271.930 489.600 ;
    END
  END r0_rd_out[117]
  PIN r0_rd_out[118]
    DIRECTION OUTPUT ;
    USE SIGNAL ;
    SHAPE ABUTMENT ;
    PORT
      LAYER met2 ;
      RECT 274.090 489.180 274.230 489.600 ;
    END
  END r0_rd_out[118]
  PIN r0_rd_out[119]
    DIRECTION OUTPUT ;
    USE SIGNAL ;
    SHAPE ABUTMENT ;
    PORT
      LAYER met2 ;
      RECT 276.390 489.180 276.530 489.600 ;
    END
  END r0_rd_out[119]
  PIN r0_rd_out[120]
    DIRECTION OUTPUT ;
    USE SIGNAL ;
    SHAPE ABUTMENT ;
    PORT
      LAYER met2 ;
      RECT 278.690 489.180 278.830 489.600 ;
    END
  END r0_rd_out[120]
  PIN r0_rd_out[121]
    DIRECTION OUTPUT ;
    USE SIGNAL ;
    SHAPE ABUTMENT ;
    PORT
      LAYER met2 ;
      RECT 280.990 489.180 281.130 489.600 ;
    END
  END r0_rd_out[121]
  PIN r0_rd_out[122]
    DIRECTION OUTPUT ;
    USE SIGNAL ;
    SHAPE ABUTMENT ;
    PORT
      LAYER met2 ;
      RECT 283.290 489.180 283.430 489.600 ;
    END
  END r0_rd_out[122]
  PIN r0_rd_out[123]
    DIRECTION OUTPUT ;
    USE SIGNAL ;
    SHAPE ABUTMENT ;
    PORT
      LAYER met2 ;
      RECT 285.590 489.180 285.730 489.600 ;
    END
  END r0_rd_out[123]
  PIN r0_rd_out[124]
    DIRECTION OUTPUT ;
    USE SIGNAL ;
    SHAPE ABUTMENT ;
    PORT
      LAYER met2 ;
      RECT 287.890 489.180 288.030 489.600 ;
    END
  END r0_rd_out[124]
  PIN r0_rd_out[125]
    DIRECTION OUTPUT ;
    USE SIGNAL ;
    SHAPE ABUTMENT ;
    PORT
      LAYER met2 ;
      RECT 290.190 489.180 290.330 489.600 ;
    END
  END r0_rd_out[125]
  PIN r0_rd_out[126]
    DIRECTION OUTPUT ;
    USE SIGNAL ;
    SHAPE ABUTMENT ;
    PORT
      LAYER met2 ;
      RECT 292.490 489.180 292.630 489.600 ;
    END
  END r0_rd_out[126]
  PIN r0_rd_out[127]
    DIRECTION OUTPUT ;
    USE SIGNAL ;
    SHAPE ABUTMENT ;
    PORT
      LAYER met2 ;
      RECT 294.790 489.180 294.930 489.600 ;
    END
  END r0_rd_out[127]
  PIN w0_addr_in[0]
    DIRECTION INPUT ;
    USE SIGNAL ;
    SHAPE ABUTMENT ;
    PORT
      LAYER met3 ;
      RECT 0.000 439.130 0.900 439.430 ;
    END
  END w0_addr_in[0]
  PIN w0_addr_in[1]
    DIRECTION INPUT ;
    USE SIGNAL ;
    SHAPE ABUTMENT ;
    PORT
      LAYER met3 ;
      RECT 0.000 445.930 0.900 446.230 ;
    END
  END w0_addr_in[1]
  PIN w0_addr_in[2]
    DIRECTION INPUT ;
    USE SIGNAL ;
    SHAPE ABUTMENT ;
    PORT
      LAYER met3 ;
      RECT 0.000 452.730 0.900 453.030 ;
    END
  END w0_addr_in[2]
  PIN w0_addr_in[3]
    DIRECTION INPUT ;
    USE SIGNAL ;
    SHAPE ABUTMENT ;
    PORT
      LAYER met3 ;
      RECT 346.400 439.130 347.300 439.430 ;
    END
  END w0_addr_in[3]
  PIN w0_addr_in[4]
    DIRECTION INPUT ;
    USE SIGNAL ;
    SHAPE ABUTMENT ;
    PORT
      LAYER met3 ;
      RECT 346.400 445.930 347.300 446.230 ;
    END
  END w0_addr_in[4]
  PIN w0_addr_in[5]
    DIRECTION INPUT ;
    USE SIGNAL ;
    SHAPE ABUTMENT ;
    PORT
      LAYER met3 ;
      RECT 346.400 452.730 347.300 453.030 ;
    END
  END w0_addr_in[5]
  PIN r0_addr_in[0]
    DIRECTION INPUT ;
    USE SIGNAL ;
    SHAPE ABUTMENT ;
    PORT
      LAYER met3 ;
      RECT 0.000 459.530 0.900 459.830 ;
    END
  END r0_addr_in[0]
  PIN r0_addr_in[1]
    DIRECTION INPUT ;
    USE SIGNAL ;
    SHAPE ABUTMENT ;
    PORT
      LAYER met3 ;
      RECT 0.000 466.330 0.900 466.630 ;
    END
  END r0_addr_in[1]
  PIN r0_addr_in[2]
    DIRECTION INPUT ;
    USE SIGNAL ;
    SHAPE ABUTMENT ;
    PORT
      LAYER met3 ;
      RECT 0.000 473.130 0.900 473.430 ;
    END
  END r0_addr_in[2]
  PIN r0_addr_in[3]
    DIRECTION INPUT ;
    USE SIGNAL ;
    SHAPE ABUTMENT ;
    PORT
      LAYER met3 ;
      RECT 346.400 459.530 347.300 459.830 ;
    END
  END r0_addr_in[3]
  PIN r0_addr_in[4]
    DIRECTION INPUT ;
    USE SIGNAL ;
    SHAPE ABUTMENT ;
    PORT
      LAYER met3 ;
      RECT 346.400 466.330 347.300 466.630 ;
    END
  END r0_addr_in[4]
  PIN r0_addr_in[5]
    DIRECTION INPUT ;
    USE SIGNAL ;
    SHAPE ABUTMENT ;
    PORT
      LAYER met3 ;
      RECT 346.400 473.130 347.300 473.430 ;
    END
  END r0_addr_in[5]
  PIN w0_we_in
    DIRECTION INPUT ;
    USE SIGNAL ;
    SHAPE ABUTMENT ;
    PORT
      LAYER met2 ;
      RECT 297.090 489.180 297.230 489.600 ;
    END
  END w0_we_in
  PIN w0_ce_in
    DIRECTION INPUT ;
    USE SIGNAL ;
    SHAPE ABUTMENT ;
    PORT
      LAYER met2 ;
      RECT 299.390 489.180 299.530 489.600 ;
    END
  END w0_ce_in
  PIN w0_clk
    DIRECTION INPUT ;
    USE SIGNAL ;
    SHAPE ABUTMENT ;
    PORT
      LAYER met2 ;
      RECT 301.690 489.180 301.830 489.600 ;
    END
  END w0_clk
  PIN r0_ce_in
    DIRECTION INPUT ;
    USE SIGNAL ;
    SHAPE ABUTMENT ;
    PORT
      LAYER met2 ;
      RECT 303.990 489.180 304.130 489.600 ;
    END
  END r0_ce_in
  PIN r0_clk
    DIRECTION INPUT ;
    USE SIGNAL ;
    SHAPE ABUTMENT ;
    PORT
      LAYER met2 ;
      RECT 306.290 489.180 306.430 489.600 ;
    END
  END r0_clk
  PIN VSS
    DIRECTION INOUT ;
    USE GROUND ;
    PORT
      LAYER met4 ;
      RECT 2.160 4.080 3.360 485.520 ;
      RECT 13.040 4.080 14.240 485.520 ;
      RECT 23.920 4.080 25.120 485.520 ;
      RECT 34.800 4.080 36.000 485.520 ;
      RECT 45.680 4.080 46.880 485.520 ;
      RECT 56.560 4.080 57.760 485.520 ;
      RECT 67.440 4.080 68.640 485.520 ;
      RECT 78.320 4.080 79.520 485.520 ;
      RECT 89.200 4.080 90.400 485.520 ;
      RECT 100.080 4.080 101.280 485.520 ;
      RECT 110.960 4.080 112.160 485.520 ;
      RECT 121.840 4.080 123.040 485.520 ;
      RECT 132.720 4.080 133.920 485.520 ;
      RECT 143.600 4.080 144.800 485.520 ;
      RECT 154.480 4.080 155.680 485.520 ;
      RECT 165.360 4.080 166.560 485.520 ;
      RECT 176.240 4.080 177.440 485.520 ;
      RECT 187.120 4.080 188.320 485.520 ;
      RECT 198.000 4.080 199.200 485.520 ;
      RECT 208.880 4.080 210.080 485.520 ;
      RECT 219.760 4.080 220.960 485.520 ;
      RECT 230.640 4.080 231.840 485.520 ;
      RECT 241.520 4.080 242.720 485.520 ;
      RECT 252.400 4.080 253.600 485.520 ;
      RECT 263.280 4.080 264.480 485.520 ;
      RECT 274.160 4.080 275.360 485.520 ;
      RECT 285.040 4.080 286.240 485.520 ;
      RECT 295.920 4.080 297.120 485.520 ;
      RECT 306.800 4.080 308.000 485.520 ;
      RECT 317.680 4.080 318.880 485.520 ;
      RECT 328.560 4.080 329.760 485.520 ;
      RECT 339.440 4.080 340.640 485.520 ;
    END
  END VSS
  PIN VDD
    DIRECTION INOUT ;
    USE POWER ;
    PORT
      LAYER met4 ;
      RECT 2.160 4.080 3.360 485.520 ;
      RECT 13.040 4.080 14.240 485.520 ;
      RECT 23.920 4.080 25.120 485.520 ;
      RECT 34.800 4.080 36.000 485.520 ;
      RECT 45.680 4.080 46.880 485.520 ;
      RECT 56.560 4.080 57.760 485.520 ;
      RECT 67.440 4.080 68.640 485.520 ;
      RECT 78.320 4.080 79.520 485.520 ;
      RECT 89.200 4.080 90.400 485.520 ;
      RECT 100.080 4.080 101.280 485.520 ;
      RECT 110.960 4.080 112.160 485.520 ;
      RECT 121.840 4.080 123.040 485.520 ;
      RECT 132.720 4.080 133.920 485.520 ;
      RECT 143.600 4.080 144.800 485.520 ;
      RECT 154.480 4.080 155.680 485.520 ;
      RECT 165.360 4.080 166.560 485.520 ;
      RECT 176.240 4.080 177.440 485.520 ;
      RECT 187.120 4.080 188.320 485.520 ;
      RECT 198.000 4.080 199.200 485.520 ;
      RECT 208.880 4.080 210.080 485.520 ;
      RECT 219.760 4.080 220.960 485.520 ;
      RECT 230.640 4.080 231.840 485.520 ;
      RECT 241.520 4.080 242.720 485.520 ;
      RECT 252.400 4.080 253.600 485.520 ;
      RECT 263.280 4.080 264.480 485.520 ;
      RECT 274.160 4.080 275.360 485.520 ;
      RECT 285.040 4.080 286.240 485.520 ;
      RECT 295.920 4.080 297.120 485.520 ;
      RECT 306.800 4.080 308.000 485.520 ;
      RECT 317.680 4.080 318.880 485.520 ;
      RECT 328.560 4.080 329.760 485.520 ;
      RECT 339.440 4.080 340.640 485.520 ;
    END
  END VDD
  OBS
    LAYER met1 ;
    RECT 0 0 347.300 489.600 ;
    LAYER met2 ;
    RECT 0 0 347.300 489.600 ;
    LAYER met3 ;
    RECT 0 0 347.300 489.600 ;
    LAYER met4 ;
    RECT 0 0 347.300 489.600 ;
  END
END fakeram_128x64_1r1w

END LIBRARY
